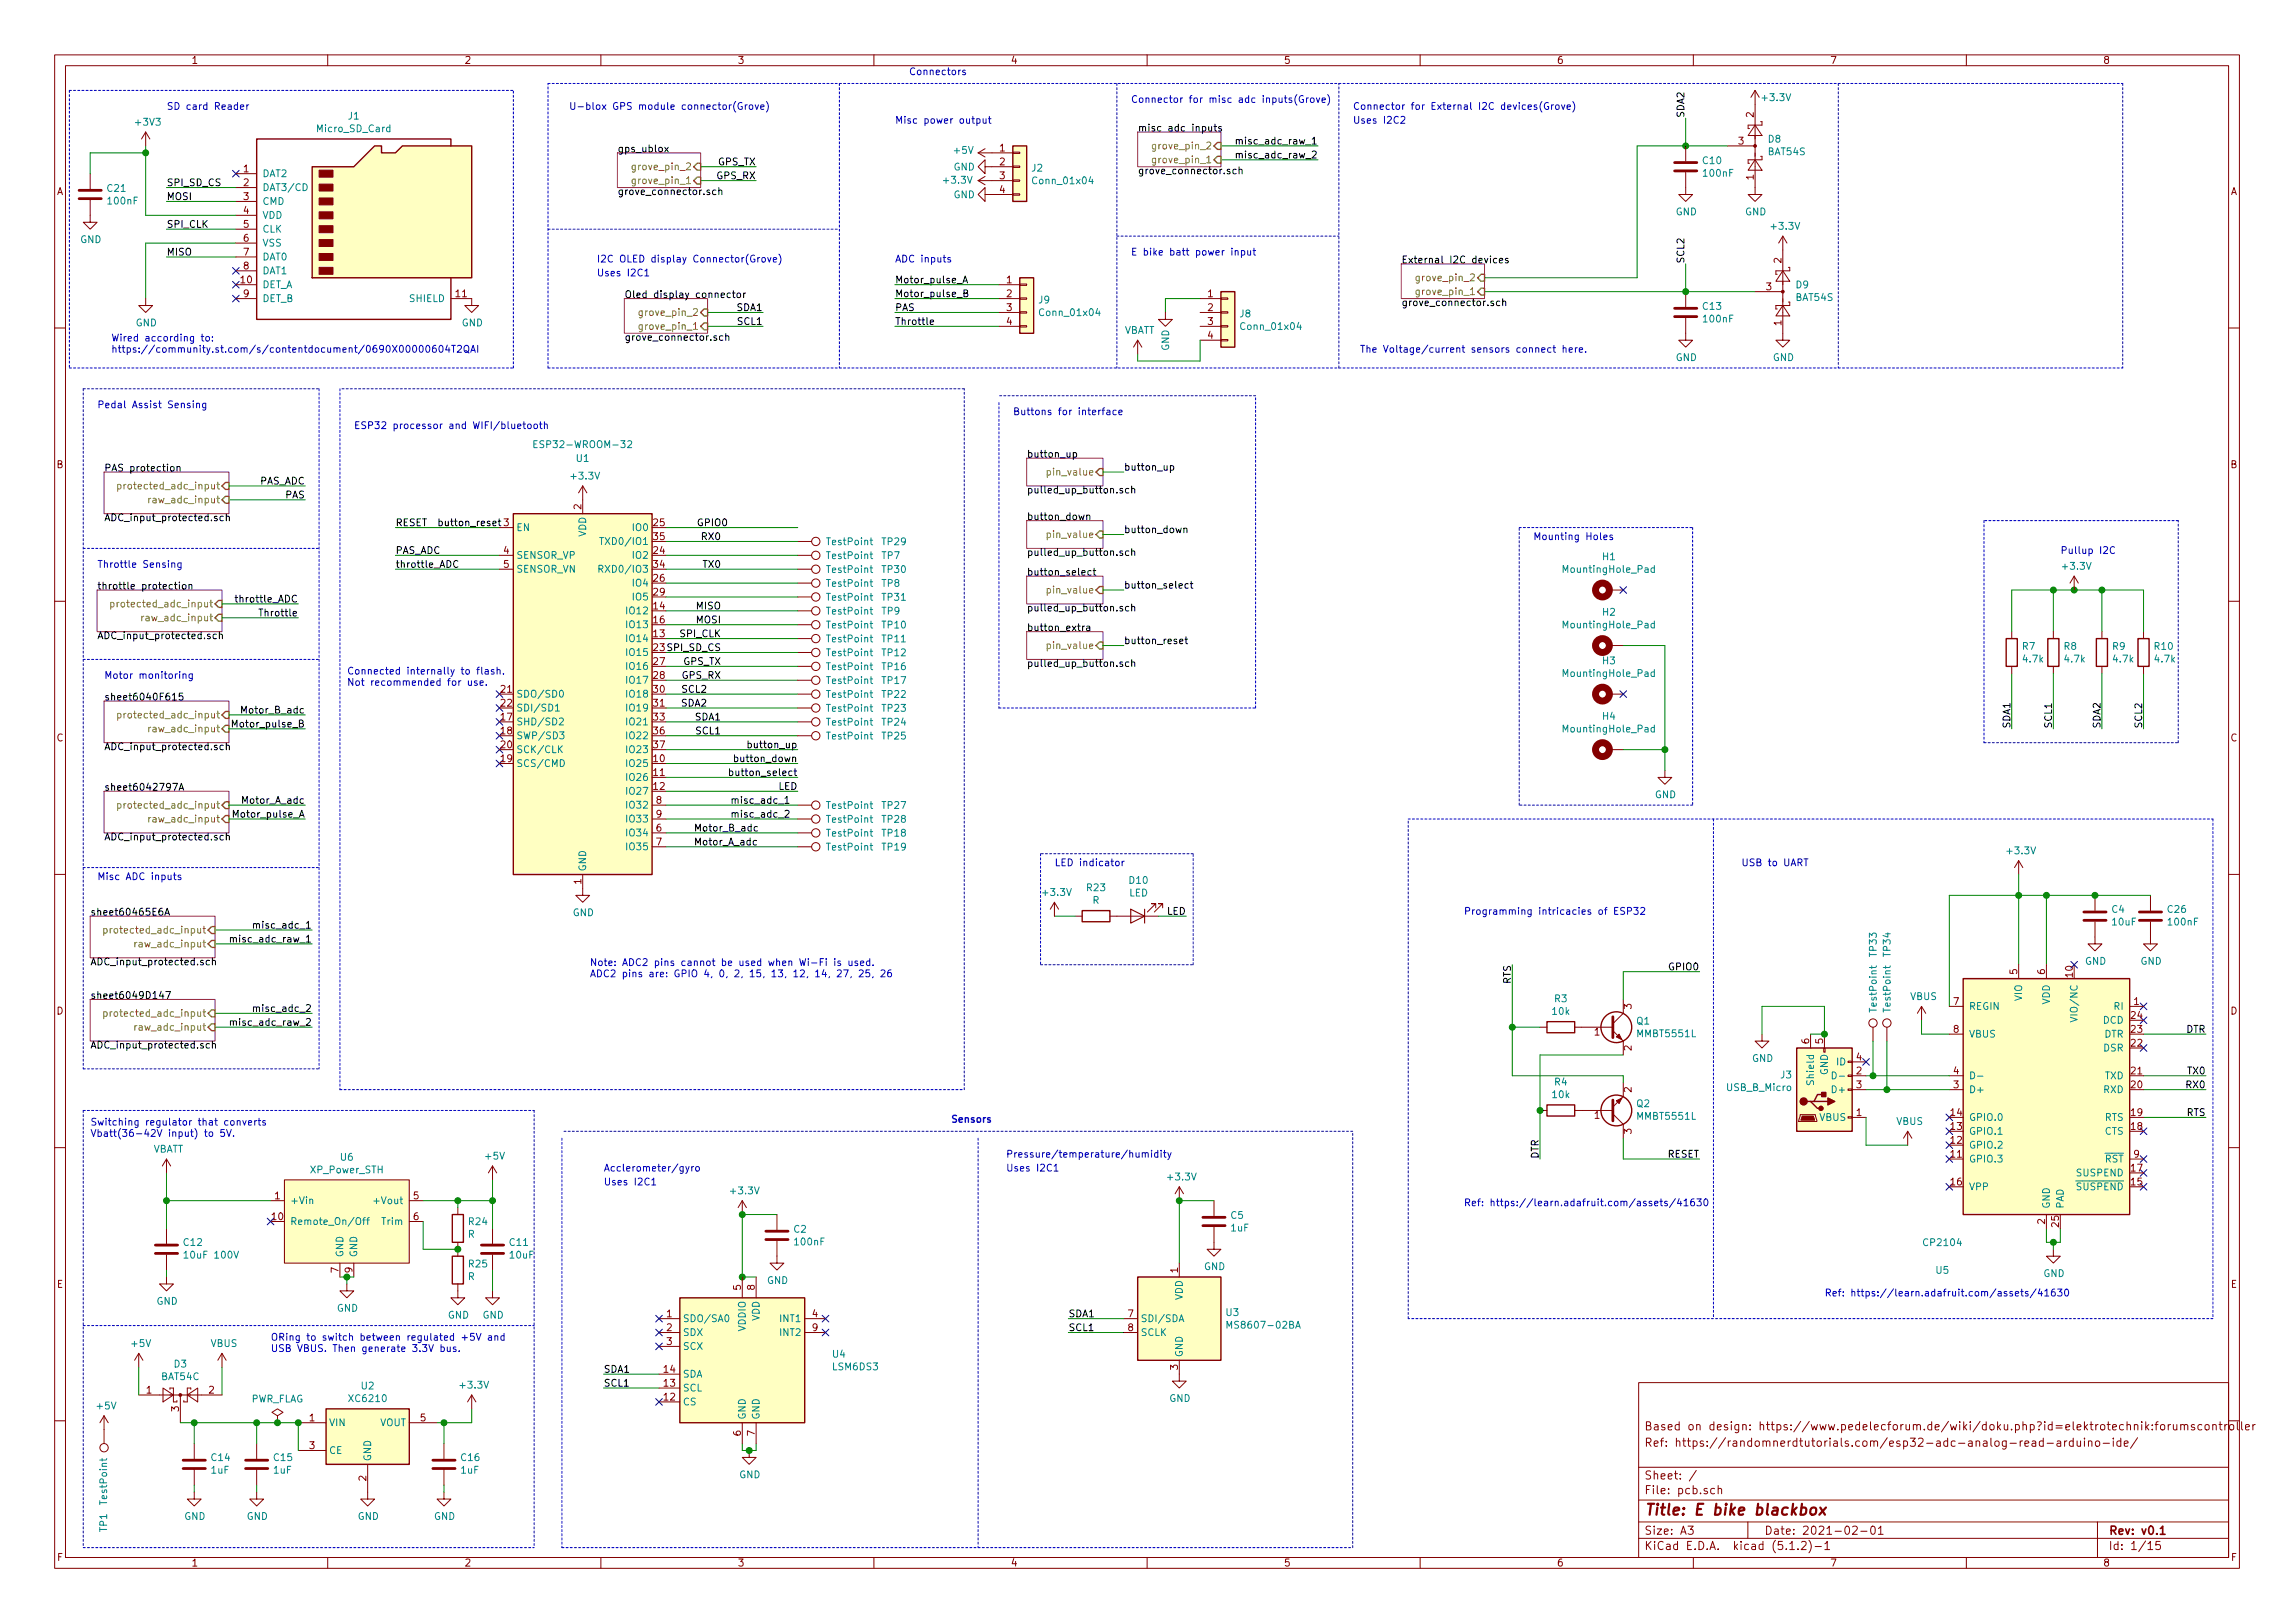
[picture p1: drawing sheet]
<svg xmlns="http://www.w3.org/2000/svg" width="420mm" height="297mm" viewBox="0 0 420 297" stroke-linecap="round" stroke-linejoin="round" font-family="sans-serif">
<defs><g id="words">
<text font-size="2.8" fill="#840000" x="301" y="277.3">Title: E bike blackbox</text>
<g font-size="2.1" fill="#840000">
<text x="301" y="261.8">Based on design: https://www.pedelecforum.de/wiki/doku.php?id=elektrotechnik:forumscontroller</text>
<text x="301" y="264.8">Ref: https://randomnerdtutorials.com/esp32-adc-analog-read-arduino-ide/</text>
<text x="301" y="273.5">File: pcb.sch</text>
<text x="301" y="270.8">Sheet: /</text>
<text x="301" y="280.9">Size: A3</text>
<text x="323" y="280.9">Date: 2021-02-01</text>
<text x="386" y="280.9">Rev: v0.1</text>
<text x="301" y="283.7">KiCad E.D.A. kicad (5.1.2)-1</text>
<text x="386" y="283.7">Id: 1/15</text>
</g>
<g font-size="1.8" fill="#840000">
<text x="35" y="11.7">1</text>
<text x="85" y="11.7">2</text>
<text x="135" y="11.7">3</text>
<text x="185" y="11.7">4</text>
<text x="235" y="11.7">5</text>
<text x="285" y="11.7">6</text>
<text x="335" y="11.7">7</text>
<text x="385" y="11.7">8</text>
<text x="321.1" y="21.5" transform="rotate(-90 321.1 21.5)">2</text>
<text x="183" y="27.7">1</text>
<text x="318.3" y="26.5">3</text>
<text x="10.4" y="35.7">A</text>
<text x="44.6" y="31.5">1</text>
<text x="44.6" y="34.1">2</text>
<text x="183" y="30.3">2</text>
<text x="183" y="32.8">3</text>
<text x="183" y="35.3">4</text>
<text x="321.1" y="32.9" transform="rotate(-90 321.1 32.9)">1</text>
<text x="408.4" y="35.7">A</text>
<text x="44.6" y="36.6">3</text>
<text x="44.6" y="39.2">4</text>
<text x="44.6" y="41.7">5</text>
<text x="44.6" y="44.2">6</text>
<text x="44.6" y="46.8">7</text>
<text x="44.1" y="51.9">10</text>
<text x="44.6" y="49.3">8</text>
<text x="184.3" y="51.9">1</text>
<text x="323.4" y="53.1">3</text>
<text x="326.1" y="48.1" transform="rotate(-90 326.1 48.1)">2</text>
<text x="44.6" y="54.4">9</text>
<text x="83.5" y="54.4">11</text>
<text x="184.3" y="54.4">2</text>
<text x="184.3" y="56.9">3</text>
<text x="184.3" y="59.5">4</text>
<text x="221.1" y="54.4">1</text>
<text x="221.1" y="56.9">2</text>
<text x="221.1" y="59.5">3</text>
<text x="326.1" y="59.6" transform="rotate(-90 326.1 59.6)">1</text>
<text x="221.1" y="62">4</text>
<text x="10.4" y="85.7">B</text>
<text x="408.4" y="85.7">B</text>
<text x="106.4" y="93.2" transform="rotate(-90 106.4 93.2)">2</text>
<text x="92.2" y="96.3">3</text>
<text x="92.2" y="101.4">4</text>
<text x="119.7" y="101.4">24</text>
<text x="119.7" y="96.3">25</text>
<text x="119.7" y="98.8">35</text>
<text x="92.2" y="103.9">5</text>
<text x="119.7" y="106.5">26</text>
<text x="119.7" y="103.9">34</text>
<text x="119.7" y="111.5">14</text>
<text x="119.7" y="109">29</text>
<text x="119.7" y="116.6">13</text>
<text x="119.7" y="114.1">16</text>
<text x="119.7" y="121.7">27</text>
<text x="119.7" y="124.2">28</text>
<text x="91.7" y="131.9">17</text>
<text x="91.7" y="126.8">21</text>
<text x="91.7" y="129.3">22</text>
<text x="119.7" y="126.8">30</text>
<text x="119.7" y="129.3">31</text>
<text x="119.7" y="131.9">33</text>
<text x="10.4" y="135.7">C</text>
<text x="91.7" y="134.4">18</text>
<text x="91.7" y="136.9">20</text>
<text x="119.7" y="134.4">36</text>
<text x="119.7" y="136.9">37</text>
<text x="408.4" y="135.7">C</text>
<text x="91.7" y="139.5">19</text>
<text x="119.7" y="139.5">10</text>
<text x="119.7" y="142">11</text>
<text x="119.7" y="144.6">12</text>
<text x="120.2" y="147.1">8</text>
<text x="120.2" y="149.6">9</text>
<text x="120.2" y="152.2">6</text>
<text x="120.2" y="154.7">7</text>
<text x="106.4" y="161.8" transform="rotate(-90 106.4 161.8)">1</text>
<text x="369.3" y="178.3" transform="rotate(-90 369.3 178.3)">5</text>
<text x="374.4" y="178.3" transform="rotate(-90 374.4 178.3)">6</text>
<text x="379.5" y="178.8" transform="rotate(-90 379.5 178.8)">10</text>
<text x="10.4" y="185.7">D</text>
<text x="298.7" y="184.7" transform="rotate(-90 298.7 184.7)">3</text>
<text x="357.7" y="183.9">7</text>
<text x="390.7" y="183.9">1</text>
<text x="408.4" y="185.7">D</text>
<text x="291.9" y="189.5">1</text>
<text x="331.2" y="191" transform="rotate(-90 331.2 191)">6</text>
<text x="333.8" y="191" transform="rotate(-90 333.8 191)">5</text>
<text x="357.7" y="189">8</text>
<text x="390.2" y="191.6">22</text>
<text x="390.2" y="189">23</text>
<text x="390.2" y="186.5">24</text>
<text x="298.7" y="192.3" transform="rotate(-90 298.7 192.3)">2</text>
<text x="339.9" y="196.6">2</text>
<text x="339.9" y="194.1">4</text>
<text x="357.7" y="196.6">4</text>
<text x="390.2" y="196.6">21</text>
<text x="298.7" y="199.9" transform="rotate(-90 298.7 199.9)">2</text>
<text x="339.9" y="199.2">3</text>
<text x="357.7" y="199.2">3</text>
<text x="390.2" y="199.2">20</text>
<text x="291.9" y="204.8">1</text>
<text x="298.7" y="207.5" transform="rotate(-90 298.7 207.5)">3</text>
<text x="339.9" y="204.3">1</text>
<text x="357.2" y="209.3">12</text>
<text x="357.2" y="206.8">13</text>
<text x="357.2" y="204.3">14</text>
<text x="390.2" y="206.8">18</text>
<text x="390.2" y="204.3">19</text>
<text x="357.2" y="211.9">11</text>
<text x="390.2" y="214.4">17</text>
<text x="390.7" y="211.9">9</text>
<text x="50.3" y="219.5">1</text>
<text x="75.7" y="219.5">5</text>
<text x="357.2" y="217">16</text>
<text x="390.2" y="217">15</text>
<text x="49.8" y="223.3">10</text>
<text x="75.7" y="223.3">6</text>
<text x="374.4" y="224" transform="rotate(-90 374.4 224)">2</text>
<text x="376.9" y="224.5" transform="rotate(-90 376.9 224.5)">25</text>
<text x="62" y="232.9" transform="rotate(-90 62 232.9)">7</text>
<text x="64.5" y="232.9" transform="rotate(-90 64.5 232.9)">9</text>
<text x="215.6" y="232.9" transform="rotate(-90 215.6 232.9)">1</text>
<text x="10.4" y="235.7">E</text>
<text x="135.6" y="236.1" transform="rotate(-90 135.6 236.1)">5</text>
<text x="138.2" y="236.1" transform="rotate(-90 138.2 236.1)">8</text>
<text x="408.4" y="235.7">E</text>
<text x="122.1" y="241.1">1</text>
<text x="122.1" y="243.6">2</text>
<text x="148.7" y="241.1">4</text>
<text x="148.7" y="243.6">9</text>
<text x="206.5" y="241.1">7</text>
<text x="206.5" y="243.6">8</text>
<text x="121.6" y="251.2">14</text>
<text x="122.1" y="246.2">3</text>
<text x="215.6" y="250.7" transform="rotate(-90 215.6 250.7)">3</text>
<text x="26.8" y="255.1">1</text>
<text x="38.3" y="255.1">2</text>
<text x="121.6" y="256.3">12</text>
<text x="121.6" y="253.8">13</text>
<text x="32.8" y="258.3" transform="rotate(-90 32.8 258.3)">3</text>
<text x="56.7" y="260.1">1</text>
<text x="77" y="260.1">5</text>
<text x="135.6" y="262.8" transform="rotate(-90 135.6 262.8)">6</text>
<text x="138.2" y="262.8" transform="rotate(-90 138.2 262.8)">7</text>
<text x="56.7" y="265.2">3</text>
<text x="67.1" y="271" transform="rotate(-90 67.1 271)">2</text>
<text x="10.5" y="285.7">F</text>
<text x="35" y="286.7">1</text>
<text x="85" y="286.7">2</text>
<text x="135" y="286.7">3</text>
<text x="185" y="286.7">4</text>
<text x="235" y="286.7">5</text>
<text x="285" y="286.7">6</text>
<text x="335" y="286.7">7</text>
<text x="385" y="286.7">8</text>
<text x="408.5" y="285.7">F</text>
</g>
<g font-size="1.8" fill="#0000c2">
<text x="166.4" y="13.8">Connectors</text>
<text x="30.5" y="20.1">SD card Reader</text>
<text x="104.1" y="20.1">U-blox GPS module connector(Grove)</text>
<text x="163.8" y="22.6">Misc power output</text>
<text x="207" y="18.8">Connector for misc adc inputs(Grove)</text>
<text x="247.6" y="20.1">Connector for External I2C devices(Grove)</text>
<text x="247.6" y="22.6">Uses I2C2</text>
<text x="207" y="46.8">E bike batt power input</text>
<text x="109.2" y="48">I2C OLED display Connector(Grove)</text>
<text x="109.2" y="50.6">Uses I2C1</text>
<text x="163.8" y="48">ADC inputs</text>
<text x="20.3" y="62.5">Wired according to:</text>
<text x="20.3" y="64.6">https://community.st.com/s/contentdocument/0690X00000604T2QAI</text>
<text x="248.9" y="64.6">The Voltage/current sensors connect here.</text>
<text x="17.8" y="74.7">Pedal Assist Sensing</text>
<text x="185.4" y="76">Buttons for interface</text>
<text x="64.8" y="78.5">ESP32 processor and WIFI/bluetooth</text>
<text x="280.7" y="98.8">Mounting Holes</text>
<text x="377.2" y="101.4">Pullup I2C</text>
<text x="17.8" y="103.9">Throttle Sensing</text>
<text x="19" y="124.2">Motor monitoring</text>
<text x="63.5" y="123.5">Connected internally to flash.</text>
<text x="63.5" y="125.5">Not recommended for use.</text>
<text x="17.8" y="161.1">Misc ADC inputs</text>
<text x="193" y="158.5">LED indicator</text>
<text x="318.8" y="158.5">USB to UART</text>
<text x="268" y="167.4">Programming intricacies of ESP32</text>
<text x="107.9" y="176.8">Note: ADC2 pins cannot be used when Wi-Fi is used.</text>
<text x="107.9" y="178.9">ADC2 pins are: GPIO 4, 0, 2, 15, 13, 12, 14, 27, 25, 26</text>
<text x="16.5" y="206">Switching regulator that converts</text>
<text x="16.5" y="208.1">Vbatt(36-42V input) to 5V.</text>
<text x="174" y="205.5">Sensors</text>
<text x="110.5" y="214.4">Acclerometer/gyro</text>
<text x="184.1" y="211.9">Pressure/temperature/humidity</text>
<text x="184.1" y="214.4">Uses I2C1</text>
<text x="110.5" y="217">Uses I2C1</text>
<text x="268" y="220.8">Ref: https://learn.adafruit.com/assets/41630</text>
<text x="334" y="237.3">Ref: https://learn.adafruit.com/assets/41630</text>
<text x="49.5" y="245.4">ORing to switch between regulated +5V and</text>
<text x="49.5" y="247.4">USB VBUS. Then generate 3.3V bus.</text>
</g>
<g font-size="1.8" fill="#008484">
<text x="25" y="23">+3V3</text>
<text x="63.8" y="21.9">J1</text>
<text x="322.8" y="18.5">+3.3V</text>
<text x="58.2" y="24.2">Micro_SD_Card</text>
<text x="174.8" y="28.2">+5V</text>
<text x="323.7" y="28.4">BAT54S</text>
<text x="323.7" y="26.1">D8</text>
<text x="19.7" y="35.1">C21</text>
<text x="48" y="32.4">DAT2</text>
<text x="48" y="35">DAT3/CD</text>
<text x="172.9" y="33.6">+3.3V</text>
<text x="174.6" y="31.2">GND</text>
<text x="188.9" y="31.4">J2</text>
<text x="189.4" y="33.7">Conn_01x04</text>
<text x="311.8" y="30">C10</text>
<text x="312" y="32.3">100nF</text>
<text x="19.9" y="37.4">100nF</text>
<text x="48" y="37.5">CMD</text>
<text x="48" y="40">VDD</text>
<text x="174.6" y="36.3">GND</text>
<text x="306.8" y="39.4">GND</text>
<text x="319.5" y="39.4">GND</text>
<text x="14.7" y="44.5">GND</text>
<text x="48" y="42.6">CLK</text>
<text x="48" y="45.1">VSS</text>
<text x="48" y="47.7">DAT0</text>
<text x="324.4" y="42">+3.3V</text>
<text x="48" y="52.7">DET_A</text>
<text x="48" y="50.2">DAT1</text>
<text x="328.8" y="52.8">D9</text>
<text x="24.8" y="59.7">GND</text>
<text x="48" y="55.3">DET_B</text>
<text x="75.1" y="55.3">SHIELD</text>
<text x="84.5" y="59.7">GND</text>
<text x="190.2" y="55.5">J9</text>
<text x="190.6" y="57.8">Conn_01x04</text>
<text x="227" y="58.1">J8</text>
<text x="311.8" y="56.7">C13</text>
<text x="312" y="59">100nF</text>
<text x="328.8" y="55.1">BAT54S</text>
<text x="205.7" y="61.1">VBATT</text>
<text x="214" y="64.2" transform="rotate(-90 214 64.2)">GND</text>
<text x="227.5" y="60.4">Conn_01x04</text>
<text x="306.8" y="66.1">GND</text>
<text x="324.6" y="66.1">GND</text>
<text x="98.8" y="82">ESP32-WROOM-32</text>
<text x="104.7" y="87.8">+3.3V</text>
<text x="105.6" y="84.5">U1</text>
<text x="94.5" y="97.2">EN</text>
<text x="107.3" y="98.3" transform="rotate(-90 107.3 98.3)">VDD</text>
<text x="111" y="99.7">TXD0/IO1</text>
<text x="116" y="97.2">IO0</text>
<text x="151.5" y="99.8">TestPoint</text>
<text x="161.6" y="99.8">TP29</text>
<text x="94.5" y="102.3">SENSOR_VP</text>
<text x="94.5" y="104.8">SENSOR_VN</text>
<text x="110.8" y="104.8">RXD0/IO3</text>
<text x="116" y="102.3">IO2</text>
<text x="116" y="107.4">IO4</text>
<text x="151.5" y="102.3">TestPoint</text>
<text x="151.5" y="107.4">TestPoint</text>
<text x="151.5" y="104.9">TestPoint</text>
<text x="161.5" y="102.3">TP7</text>
<text x="161.5" y="107.4">TP8</text>
<text x="161.6" y="104.9">TP30</text>
<text x="286.5" y="104.8">MountingHole_Pad</text>
<text x="293.4" y="102.5">H1</text>
<text x="377.8" y="104.3">+3.3V</text>
<text x="115" y="112.4">IO12</text>
<text x="116" y="109.9">IO5</text>
<text x="151.5" y="112.5">TestPoint</text>
<text x="151.5" y="109.9">TestPoint</text>
<text x="161.5" y="112.5">TP9</text>
<text x="161.6" y="109.9">TP31</text>
<text x="293.4" y="112.7">H2</text>
<text x="115" y="117.5">IO14</text>
<text x="115" y="115">IO13</text>
<text x="151.5" y="115">TestPoint</text>
<text x="151.5" y="117.6">TestPoint</text>
<text x="161.6" y="115">TP10</text>
<text x="161.6" y="117.6">TP11</text>
<text x="286.5" y="115">MountingHole_Pad</text>
<text x="370.3" y="118.9">R7</text>
<text x="377.9" y="118.9">R8</text>
<text x="386.8" y="118.9">R9</text>
<text x="394.5" y="118.9">R10</text>
<text x="115" y="120.1">IO15</text>
<text x="115" y="122.6">IO16</text>
<text x="115" y="125.1">IO17</text>
<text x="151.5" y="120.1">TestPoint</text>
<text x="151.5" y="125.2">TestPoint</text>
<text x="151.5" y="122.6">TestPoint</text>
<text x="161.6" y="120.1">TP12</text>
<text x="161.6" y="125.2">TP17</text>
<text x="161.6" y="122.6">TP16</text>
<text x="286.5" y="123.9">MountingHole_Pad</text>
<text x="293.4" y="121.6">H3</text>
<text x="370.5" y="121.2">4.7k</text>
<text x="378.1" y="121.2">4.7k</text>
<text x="387" y="121.2">4.7k</text>
<text x="394.6" y="121.2">4.7k</text>
<text x="94.5" y="127.7">SDO/SD0</text>
<text x="94.5" y="130.2">SDI/SD1</text>
<text x="115" y="127.7">IO18</text>
<text x="115" y="130.2">IO19</text>
<text x="151.5" y="130.3">TestPoint</text>
<text x="151.5" y="127.7">TestPoint</text>
<text x="161.6" y="130.3">TP23</text>
<text x="161.6" y="127.7">TP22</text>
<text x="293.4" y="131.7">H4</text>
<text x="94.5" y="132.8">SHD/SD2</text>
<text x="94.5" y="135.3">SWP/SD3</text>
<text x="94.5" y="137.8">SCK/CLK</text>
<text x="115" y="132.8">IO21</text>
<text x="115" y="135.3">IO22</text>
<text x="115" y="137.8">IO23</text>
<text x="151.5" y="135.3">TestPoint</text>
<text x="151.5" y="132.8">TestPoint</text>
<text x="161.6" y="135.3">TP25</text>
<text x="161.6" y="132.8">TP24</text>
<text x="286.5" y="134">MountingHole_Pad</text>
<text x="94.5" y="140.4">SCS/CMD</text>
<text x="115" y="140.4">IO25</text>
<text x="115" y="142.9">IO26</text>
<text x="115" y="145.5">IO27</text>
<text x="115" y="148">IO32</text>
<text x="151.5" y="148">TestPoint</text>
<text x="161.6" y="148">TP27</text>
<text x="303" y="146.1">GND</text>
<text x="115" y="153.1">IO34</text>
<text x="115" y="155.6">IO35</text>
<text x="115" y="150.5">IO33</text>
<text x="151.5" y="153.1">TestPoint</text>
<text x="151.5" y="155.7">TestPoint</text>
<text x="151.5" y="150.6">TestPoint</text>
<text x="161.6" y="153.1">TP18</text>
<text x="161.6" y="155.7">TP19</text>
<text x="161.6" y="150.6">TP28</text>
<text x="107.3" y="159.5" transform="rotate(-90 107.3 159.5)">GND</text>
<text x="206.8" y="161.8">D10</text>
<text x="367.6" y="156.3">+3.3V</text>
<text x="104.9" y="167.7">GND</text>
<text x="191.1" y="164">+3.3V</text>
<text x="199" y="163.1">R23</text>
<text x="200" y="165.4">R</text>
<text x="206.7" y="164.1">LED</text>
<text x="386.7" y="167.1">C4</text>
<text x="396.9" y="167.1">C26</text>
<text x="386.8" y="169.4">10uF</text>
<text x="397.1" y="169.4">100nF</text>
<text x="343.6" y="175" transform="rotate(-90 343.6 175)">TP33</text>
<text x="346.1" y="175" transform="rotate(-90 346.1 175)">TP34</text>
<text x="381.7" y="176.6">GND</text>
<text x="391.9" y="176.6">GND</text>
<text x="284.3" y="185.7">10k</text>
<text x="284.6" y="183.4">R3</text>
<text x="343.6" y="185" transform="rotate(-90 343.6 185)">TestPoint</text>
<text x="346.1" y="185" transform="rotate(-90 346.1 185)">TestPoint</text>
<text x="349.7" y="183">VBUS</text>
<text x="360.4" y="184.8">REGIN</text>
<text x="370.2" y="183.2" transform="rotate(-90 370.2 183.2)">VIO</text>
<text x="375.3" y="183.9" transform="rotate(-90 375.3 183.9)">VDD</text>
<text x="387.1" y="184.8">RI</text>
<text x="299.7" y="187.5">Q1</text>
<text x="299.9" y="189.8">MMBT5551L</text>
<text x="360.4" y="189.9">VBUS</text>
<text x="380.4" y="186.2" transform="rotate(-90 380.4 186.2)">VIO/NC</text>
<text x="385" y="187.4">DCD</text>
<text x="385.2" y="189.9">DTR</text>
<text x="320.8" y="194.3">GND</text>
<text x="326" y="197.4">J3</text>
<text x="334.6" y="196.8" transform="rotate(-90 334.6 196.8)">GND</text>
<text x="336.3" y="195">ID</text>
<text x="385.1" y="192.4">DSR</text>
<text x="385.3" y="197.5">TXD</text>
<text x="284.3" y="201">10k</text>
<text x="284.6" y="198.7">R4</text>
<text x="299.7" y="202.6">Q2</text>
<text x="316.2" y="199.7">USB_B_Micro</text>
<text x="332.1" y="198.1" transform="rotate(-90 332.1 198.1)">Shield</text>
<text x="335.8" y="200.1">D+</text>
<text x="360.4" y="200.1">D+</text>
<text x="385.1" y="200.1">RXD</text>
<text x="299.9" y="204.9">MMBT5551L</text>
<text x="333.2" y="205.1">VBUS</text>
<text x="347.2" y="205.9">VBUS</text>
<text x="360.4" y="207.7">GPIO.1</text>
<text x="360.4" y="205.1">GPIO.0</text>
<text x="385.3" y="207.7">CTS</text>
<text x="385.3" y="205.1">RTS</text>
<text x="27.9" y="211">VBATT</text>
<text x="56.9" y="214.7">XP_Power_STH</text>
<text x="62.4" y="212.4">U6</text>
<text x="89" y="212.2">+5V</text>
<text x="360.4" y="212.8">GPIO.3</text>
<text x="360.4" y="210.2">GPIO.2</text>
<text x="380.3" y="215.3">SUSPEND</text>
<text x="385.3" y="212.8">RST</text>
<text x="53.1" y="220.4">+Vin</text>
<text x="69" y="220.4">+Vout</text>
<text x="133.9" y="218.6">+3.3V</text>
<text x="213.9" y="216">+3.3V</text>
<text x="360.4" y="217.8">VPP</text>
<text x="375.3" y="221.3" transform="rotate(-90 375.3 221.3)">GND</text>
<text x="377.8" y="221.3" transform="rotate(-90 377.8 221.3)">PAD</text>
<text x="380.3" y="217.8">SUSPEND</text>
<text x="53.1" y="224.2">Remote_On/Off</text>
<text x="70.1" y="224.2">Trim</text>
<text x="85.7" y="226.5">R</text>
<text x="85.9" y="224.2">R24</text>
<text x="145.4" y="225.6">C2</text>
<text x="145.6" y="227.9">100nF</text>
<text x="225.4" y="223.1">C5</text>
<text x="225.4" y="225.4">1uF</text>
<text x="33.7" y="228">C12</text>
<text x="34.3" y="230.3">10uF 100V</text>
<text x="62.9" y="230.2" transform="rotate(-90 62.9 230.2)">GND</text>
<text x="65.4" y="230.2" transform="rotate(-90 65.4 230.2)">GND</text>
<text x="85.9" y="232">R25</text>
<text x="93.4" y="228">C11</text>
<text x="93.4" y="230.3">10uF</text>
<text x="220.4" y="232.4">GND</text>
<text x="352.4" y="228.1">CP2104</text>
<text x="354.5" y="233.1">U5</text>
<text x="374.1" y="233.7">GND</text>
<text x="28.7" y="238.8">GND</text>
<text x="85.7" y="234.3">R</text>
<text x="140.4" y="235">GND</text>
<text x="216.5" y="238" transform="rotate(-90 216.5 238)">VDD</text>
<text x="61.7" y="240.1">GND</text>
<text x="82" y="241.3">GND</text>
<text x="88.3" y="241.3">GND</text>
<text x="125" y="242">SDO/SA0</text>
<text x="125" y="244.5">SDX</text>
<text x="136.5" y="243.6" transform="rotate(-90 136.5 243.6)">VDDIO</text>
<text x="139.1" y="241.8" transform="rotate(-90 139.1 241.8)">VDD</text>
<text x="143" y="242">INT1</text>
<text x="143" y="244.5">INT2</text>
<text x="208.8" y="242">SDI/SDA</text>
<text x="208.8" y="244.5">SCLK</text>
<text x="224.5" y="240.9">U3</text>
<text x="225.4" y="243.2">MS8607-02BA</text>
<text x="24.2" y="246.5">+5V</text>
<text x="31.9" y="250.3">D3</text>
<text x="38.6" y="246.5">VBUS</text>
<text x="125" y="247.1">SCX</text>
<text x="152.5" y="248.5">U4</text>
<text x="152.6" y="250.8">LSM6DS3</text>
<text x="216.5" y="248.4" transform="rotate(-90 216.5 248.4)">GND</text>
<text x="17.8" y="257.9">+5V</text>
<text x="29.6" y="252.6">BAT54C</text>
<text x="45.8" y="256.7">PWR_FLAG</text>
<text x="64.1" y="256.6">XC6210</text>
<text x="66.2" y="254.3">U2</text>
<text x="84.4" y="254.1">+3.3V</text>
<text x="125" y="257.2">CS</text>
<text x="125" y="254.7">SCL</text>
<text x="125" y="252.1">SDA</text>
<text x="214.1" y="256.6">GND</text>
<text x="60.2" y="261">VIN</text>
<text x="69.5" y="261">VOUT</text>
<text x="136.5" y="259.9" transform="rotate(-90 136.5 259.9)">GND</text>
<text x="139.1" y="259.9" transform="rotate(-90 139.1 259.9)">GND</text>
<text x="38.7" y="269.7">1uF</text>
<text x="38.8" y="267.4">C14</text>
<text x="50.1" y="269.7">1uF</text>
<text x="50.2" y="267.4">C15</text>
<text x="60.2" y="266.1">CE</text>
<text x="67.9" y="267.5" transform="rotate(-90 67.9 267.5)">GND</text>
<text x="84.4" y="269.7">1uF</text>
<text x="84.5" y="267.4">C16</text>
<text x="19.6" y="275.2" transform="rotate(-90 19.6 275.2)">TestPoint</text>
<text x="135.3" y="270.5">GND</text>
<text x="19.6" y="280.3" transform="rotate(-90 19.6 280.3)">TP1</text>
<text x="33.7" y="278.2">GND</text>
<text x="45.2" y="278.2">GND</text>
<text x="65.5" y="278.2">GND</text>
<text x="79.5" y="278.2">GND</text>
</g>
<g font-size="1.8">
<text x="308.4" y="21.6" transform="rotate(-90 308.4 21.6)">SDA2</text>
<text x="113" y="27.9">gps_ublox</text>
<text x="208.3" y="24.1">misc adc inputs</text>
<text x="227.2" y="26.5">misc_adc_raw_1</text>
<text x="227.2" y="29">misc_adc_raw_2</text>
<text x="30.5" y="34.1">SPI_SD_CS</text>
<text x="113" y="35.7">grove_connector.sch</text>
<text x="131.2" y="32.8">GPS_RX</text>
<text x="131.4" y="30.3">GPS_TX</text>
<text x="208.3" y="31.9">grove_connector.sch</text>
<text x="30.5" y="41.7">SPI_CLK</text>
<text x="30.5" y="36.6">MOSI</text>
<text x="30.5" y="46.8">MISO</text>
<text x="163.8" y="51.9">Motor_pulse_A</text>
<text x="256.5" y="48.2">External I2C devices</text>
<text x="308.4" y="48.3" transform="rotate(-90 308.4 48.3)">SCL2</text>
<text x="114.3" y="54.5">Oled display connector</text>
<text x="135" y="56.9">SDA1</text>
<text x="135.2" y="59.5">SCL1</text>
<text x="163.8" y="59.5">Throttle</text>
<text x="163.8" y="56.9">PAS</text>
<text x="163.8" y="54.4">Motor_pulse_B</text>
<text x="256.5" y="56">grove_connector.sch</text>
<text x="114.3" y="62.4">grove_connector.sch</text>
<text x="188" y="83.8">button_up</text>
<text x="19" y="86.3">PAS protection</text>
<text x="47.4" y="88.7">PAS_ADC</text>
<text x="205.7" y="86.1">button_up</text>
<text x="19" y="95.4">ADC_input_protected.sch</text>
<text x="52.2" y="91.2">PAS</text>
<text x="188" y="90.3">pulled_up_button.sch</text>
<text x="188" y="95.2">button_down</text>
<text x="72.4" y="101.4">PAS_ADC</text>
<text x="72.4" y="96.3">RESET</text>
<text x="80" y="96.3">button_reset</text>
<text x="127.9" y="96.3">GPIO0</text>
<text x="128.7" y="98.8">RX0</text>
<text x="188" y="101.7">pulled_up_button.sch</text>
<text x="205.7" y="97.6">button_down</text>
<text x="17.8" y="107.9">throttle protection</text>
<text x="72.4" y="103.9">throttle_ADC</text>
<text x="128.8" y="103.9">TX0</text>
<text x="188" y="105.3">button_select</text>
<text x="205.7" y="107.7">button_select</text>
<text x="43.7" y="110.3">throttle_ADC</text>
<text x="48" y="112.8">Throttle</text>
<text x="127.6" y="111.5">MISO</text>
<text x="188" y="111.9">pulled_up_button.sch</text>
<text x="17.8" y="117">ADC_input_protected.sch</text>
<text x="119.7" y="119.2">23 SPI_SD_CS</text>
<text x="124.6" y="116.6">SPI_CLK</text>
<text x="127.6" y="114.1">MOSI</text>
<text x="188" y="115.5">button_extra</text>
<text x="205.7" y="117.9">button_reset</text>
<text x="124.9" y="124.2">GPS_RX</text>
<text x="125.1" y="121.7">GPS_TX</text>
<text x="188" y="122.1">pulled_up_button.sch</text>
<text x="19" y="128.2">sheet6040F615</text>
<text x="44.7" y="130.6">Motor_B_adc</text>
<text x="124.8" y="129.3">SDA2</text>
<text x="125" y="126.8">SCL2</text>
<text x="127.4" y="131.9">SDA1</text>
<text x="19" y="137.3">ADC_input_protected.sch</text>
<text x="43.1" y="133.1">Motor_pulse_B</text>
<text x="127.6" y="134.4">SCL1</text>
<text x="137.4" y="136.9">button_up</text>
<text x="368" y="133.4" transform="rotate(-90 368 133.4)">SDA1</text>
<text x="375.7" y="133.4" transform="rotate(-90 375.7 133.4)">SCL1</text>
<text x="384.6" y="133.4" transform="rotate(-90 384.6 133.4)">SDA2</text>
<text x="392.2" y="133.4" transform="rotate(-90 392.2 133.4)">SCL2</text>
<text x="134.5" y="142">button_select</text>
<text x="135" y="139.5">button_down</text>
<text x="19" y="144.7">sheet6042797A</text>
<text x="43.1" y="149.6">Motor_pulse_A</text>
<text x="44.7" y="147.1">Motor_A_adc</text>
<text x="134.7" y="147.1">misc_adc_1</text>
<text x="134.7" y="149.6">misc_adc_2</text>
<text x="142.5" y="144.6">LED</text>
<text x="19" y="153.8">ADC_input_protected.sch</text>
<text x="127" y="152.2">Motor_B_adc</text>
<text x="127" y="154.7">Motor_A_adc</text>
<text x="16.5" y="167.6">sheet60465E6A</text>
<text x="213.6" y="167.4">LED</text>
<text x="43.1" y="172.5">misc_adc_raw_1</text>
<text x="47.1" y="170">misc_adc_1</text>
<text x="16.5" y="176.7">ADC_input_protected.sch</text>
<text x="305.7" y="177.6">GPIO0</text>
<text x="16.5" y="182.8">sheet6049D147</text>
<text x="47.1" y="185.2">misc_adc_2</text>
<text x="276.6" y="180.1" transform="rotate(-90 276.6 180.1)">RTS</text>
<text x="16.5" y="191.9">ADC_input_protected.sch</text>
<text x="43.1" y="187.7">misc_adc_raw_2</text>
<text x="400.2" y="189">DTR</text>
<text x="400.6" y="196.6">TX0</text>
<text x="400.4" y="199.2">RX0</text>
<text x="400.3" y="204.3">RTS</text>
<text x="281.7" y="212.1" transform="rotate(-90 281.7 212.1)">DTR</text>
<text x="305.3" y="211.9">RESET</text>
<text x="195.6" y="243.6">SCL1</text>
<text x="195.6" y="241.1">SDA1</text>
<text x="110.5" y="251.2">SDA1</text>
<text x="110.5" y="253.8">SCL1</text>
</g>
<g font-size="1.8" fill="#848400">
<text x="211.6" y="29.9">grove_pin_1</text>
<text x="211.6" y="27.3">grove_pin_2</text>
<text x="116.3" y="33.7">grove_pin_1</text>
<text x="116.3" y="31.2">grove_pin_2</text>
<text x="259.8" y="51.5">grove_pin_2</text>
<text x="117.6" y="57.8">grove_pin_2</text>
<text x="259.8" y="54">grove_pin_1</text>
<text x="117.6" y="60.4">grove_pin_1</text>
<text x="23" y="89.6">protected_adc_input</text>
<text x="192.3" y="87">pin_value</text>
<text x="28" y="92.1">raw_adc_input</text>
<text x="192.3" y="98.5">pin_value</text>
<text x="21.7" y="111.2">protected_adc_input</text>
<text x="26.7" y="113.7">raw_adc_input</text>
<text x="192.3" y="108.6">pin_value</text>
<text x="192.3" y="118.8">pin_value</text>
<text x="23" y="131.5">protected_adc_input</text>
<text x="28" y="134">raw_adc_input</text>
<text x="23" y="148">protected_adc_input</text>
<text x="28" y="150.5">raw_adc_input</text>
<text x="20.4" y="170.9">protected_adc_input</text>
<text x="25.5" y="173.4">raw_adc_input</text>
<text x="20.4" y="186.1">protected_adc_input</text>
<text x="25.5" y="188.6">raw_adc_input</text>
</g>
</g></defs>
<g fill="none" stroke="#840000" stroke-width=".18">
<path d="M10 10h400v277h-400zM12 12h396v273.1h-396zM60 10v2M110 10v2M160 10v2M210 10v2M260 10v2M310 10v2M321.3 16.5v19.1h1.3l-1.3 1.3-1.3-1.3h1.3M321.3 16.5l-.8 1.3M321.3 16.5l.8 1.3M360 10v2"/>
<path d="M16.5 36.6v4.1h1.3l-1.3 1.2-1.3-1.2h1.3M16.5 31.8v2.8M26.7 24.2l-.8 1.2M26.7 24.2v2.5M26.7 24.2l.7 1.2M43.2 31.8h3.8M43.2 34.3h3.8M43.2 36.9h3.8M43.2 39.4h3.8M179.1 28l1.2 .7M179.1 28h6.3M179.1 33.1l1.2 .7"/>
<path d="M179.1 33.1h6.3M180.3 30.5v-1.3l-1.2 1.3 1.2 1.3v-1.3h5.1M180.3 35.6v-1.3l-1.2 1.3 1.2 1.3v-1.3h5.1M180.3 27.2l-1.2 .8M180.3 32.3l-1.2 .8M185.4 35.5h1.3v.2h-1.3zM185.4 32.9h1.3v.3h-1.3zM185.4 30.4h1.3v.2h-1.3zM185.4 27.8h1.3v.3h-1.3zM308.6 31.5v4.1h1.3l-1.3 1.3-1.3-1.3h1.3M308.6 26.7v2.8M316.2 26.7h5.1"/>
<path d="M321.3 29.2l1.3 2h-2.6zM321.3 22.9l1.3 1.9h-2.6zM322.3 28.6h.3v.6h-2.6v.7h.3M322.3 22.3h.3v.6h-2.6v.6h.3M26.7 54.6v1.3h1.2l-1.2 1.3-1.3-1.3h1.3M43.2 52.1h3.8M43.2 54.6h3.8M43.2 41.9h3.8M43.2 44.5h3.8M43.2 47h3.8M43.2 49.6h3.8M82.5 54.6h3.9v1.3h1.2l-1.2 1.3-1.3-1.3h1.3"/>
<path d="M182.9 52.1h3.8M182.9 54.6h3.8M182.9 57.2h3.8M182.9 59.7h3.8M186.7 59.6h1.3v.3h-1.3zM186.7 57.1h1.3v.2h-1.3zM186.7 54.5h1.3v.3h-1.3zM186.7 52h1.3v.2h-1.3zM213.4 57.2v1.3h1.2l-1.2 1.2-1.3-1.2h1.3M219.7 54.6h3.8M219.7 57.2h3.8M219.7 59.7h3.8"/>
<path d="M223.5 59.6h1.3v.3h-1.3zM223.5 57.1h1.3v.2h-1.3zM223.5 54.5h1.3v.3h-1.3zM308.6 58.2v4.1h1.3l-1.3 1.2-1.3-1.2h1.3M308.6 53.4v2.8M321.3 53.4h5.1M326.4 43.2v19.1h1.3l-1.3 1.2-1.3-1.2h1.3M326.4 55.9l1.3 1.9h-2.6zM326.4 49.6l1.3 1.9h-2.6zM326.4 43.2l-.8 1.3M326.4 43.2l.8 1.3M327.4 48.9h.3v.7h-2.6v.6h.3"/>
<path d="M327.4 55.3h.3v.6h-2.6v.7h.3M10 60h2M208.3 62.3l-.8 1.2M208.3 62.3v2.5M208.3 62.3l.7 1.2M219.7 62.3h3.8M223.5 62.1h1.3v.3h-1.3zM408 60h2M91.4 96.6h2.6M106.7 88.9v5.1M106.7 88.9l-.8 1.3M106.7 88.9l.7 1.3"/>
<path d="M146 99.1h2.6M10 110h2M91.4 101.6h2.6M91.4 104.2h2.6M146 111.8h2.6M146 114.3h2.6M146 116.9h2.6M146 119.4h2.6M146 101.6h2.6M146 106.7h2.6M146 109.3h2.6M146 104.2h2.6"/>
<path d="M294.6 108h2.6M294.6 118.1h2.6M368.3 115.6v1.3M375.9 115.6v1.3M379.7 105.4l-.7 1.3M379.7 105.4v2.6M379.7 105.4l.8 1.3M384.8 115.6v1.3M392.4 115.6v1.3M408 110h2M146 127h2.6M146 129.6h2.6"/>
<path d="M146 124.5h2.6M146 122h2.6M146 134.7h2.6M146 132.1h2.6M294.6 127h2.6M294.6 137.2h2.6M368.3 122v1.2M375.9 122v1.2M384.8 122v1.2M392.4 122v1.2M119.4 152.4h2.5M119.4 155h2.5"/>
<path d="M119.4 149.9h2.5M119.4 147.4h2.5M146 152.4h2.6M146 155h2.6M146 149.9h2.6M146 147.4h2.6M304.8 141v1.3h1.3l-1.3 1.2-1.3-1.2h1.3M369.6 157.5l-.8 1.3M369.6 157.5v2.6M369.6 157.5l.7 1.3M10 160h2M106.7 160.1v3.8h1.2l-1.2 1.2-1.3-1.2h1.3"/>
<path d="M193 165.1l-.7 1.3M193 165.1v2.6M193 165.1l.8 1.3M196.8 167.7h1.3M203.2 167.7h8.9M211.6 166.2v-.8h-.8h.8l-1.5 1.5M212.9 166.2v-.8h-.8h.8l-1.6 1.5M369.6 176.6v2.5M374.6 176.6v2.5M383.5 168.7v4.1h1.3l-1.3 1.2-1.2-1.2h1.2M383.5 163.9v2.8M393.7 168.7v4.1h1.3l-1.3 1.2-1.3-1.2h1.3"/>
<path d="M393.7 163.9v2.8M408 160h2M281.9 188h1.3M288.3 188h7M295.3 188.6l1.9 1.9v2.6M297.2 198.2v2.5l-1.9 1.9M297.2 182.9v2.6l-1.9 1.9M322.6 189.3v1.2h1.2l-1.2 1.3-1.3-1.3h1.3M331.5 189.3v2.5M333.9 191.8h.2v.8h-.2zM334 189.3v2.5M338.3 194.2h.8v.3h-.8z"/>
<path d="M338.3 196.8h.8v.2h-.8zM338.3 199.3h.8v.3h-.8zM339.1 199.4h2.5M339.1 196.9h2.5M339.1 194.3h2.5M342.9 188v2.5M345.4 188v2.5M351.8 184.2l-.8 1.3M351.8 184.2v2.5M351.8 184.2l.8 1.3M356.9 184.2h2.5M356.9 199.4h2.5"/>
<path d="M356.9 196.9h2.5M356.9 189.3h2.5M389.9 184.2h2.5M10 210h2M30.5 212.1v2.6M30.5 212.1l-.8 1.3M30.5 212.1l.7 1.3M49.5 219.7h2.6M52.1 215.9h22.8v15.3h-22.8zM74.9 219.7h2.6M90.2 213.4v2.5M90.2 213.4l-.8 1.3"/>
<path d="M90.2 213.4l.7 1.3M135.9 219.7l-.8 1.3M135.9 219.7v2.6M135.9 219.7l.8 1.3M215.9 217.2l-.8 1.3M215.9 217.2v2.5M215.9 217.2l.8 1.3M222.2 219.7v2.8M281.9 203.2h1.3M288.3 203.2h7M295.3 203.9l1.9 1.9v2.5M329.6 204h2.8l.2 1.3h-3.3z"/>
<path d="M338.3 204.4h.8v.2h-.8zM339.1 204.5h2.5M349.2 207l-.7 1.3M349.2 207v2.6M349.2 207l.8 1.3M389.9 212.1h2.5M408 210h2M30.5 233.7v1.3h1.2l-1.2 1.3-1.3-1.3h1.3M30.5 224.8v2.8M30.5 229.7v2.7M62.2 231.2v2.5M63.5 235v1.3h1.3l-1.3 1.2-1.3-1.2h1.3"/>
<path d="M64.8 231.2v2.5M74.9 223.6h2.6M83.8 235v2.5h1.3l-1.3 1.3-1.3-1.3h1.3M83.8 221v1.3M83.8 227.4v2.5M90.2 236.3v1.2h1.2l-1.2 1.3-1.3-1.3h1.3M90.2 224.8v2.8M90.2 229.7v2.7M135.9 233.7v3.8M138.4 233.7v3.8M142.2 227.1v4.1h1.3l-1.3 1.2-1.2-1.2h1.2M142.2 222.3v2.8"/>
<path d="M215.9 231.2v2.5M222.2 224.6v4h1.3l-1.3 1.3-1.2-1.3h1.2M374.6 222.3v2.5M375.9 228.6v1.3h1.3l-1.3 1.3-1.3-1.3h1.3M19 259.1v5.1M19 259.1l-.7 1.3M19 259.1l.8 1.3M25.4 247.7l-.8 1.3M25.4 247.7v2.5M25.4 247.7l.8 1.3M25.4 255.3h15.2M29.8 254l1.9 1.3-1.9 1.3z"/>
<path d="M31.1 254.3v-.3h.6v2.6h.7v-.3M33 255.3v5.1M34.3 255.3l1.9-1.3v2.6zM34.9 254.3v-.3h-.6v2.6h-.6v-.3M40.6 247.7l-.7 1.3M40.6 247.7v2.5M40.6 247.7l.8 1.3M50.8 259.1l1-.6-1-.7-1 .7 1 .6v1.3M86.4 255.3l-.8 1.3M86.4 255.3v2.5M86.4 255.3l.7 1.3M120.6 241.3h3.9"/>
<path d="M120.6 256.6h3.9M120.6 254h3.9M120.6 251.5h3.9M120.6 243.9h3.9M120.6 246.4h3.9M147.3 241.3h3.8M147.3 243.9h3.8M205.7 241.3h2.6M205.7 243.9h2.6M215.9 249v3.8h1.3l-1.3 1.2-1.3-1.2h1.3M300 253h108v32.1h-108zM10 260h2"/>
<path d="M35.6 273.1v1.3h1.2l-1.2 1.2-1.3-1.2h1.3M35.6 264.2v2.8M35.6 269v2.8M47 273.1v1.3h1.3l-1.3 1.2-1.3-1.2h1.3M47 264.2v2.8M47 269v2.8M50.8 260.4h.1M54.6 260.4h5.1M54.6 265.5h5.1M67.3 268v6.4h1.3l-1.3 1.2-1.3-1.2h1.3M74.9 260.4h5.1M81.3 273.1v1.3h1.2l-1.2 1.2-1.3-1.2h1.3"/>
<path d="M81.3 264.2v2.8M81.3 269v2.8M135.9 260.4v3.8M137.2 265.5v1.2h1.2l-1.2 1.3-1.3-1.3h1.3M138.4 260.4v3.8M300 278.5h108M300 274.5h108M300 268.5h108M309 279.3h1l-.5 .6 .4 .1v.7l-.2 .1-.7-.1M310.5 269.1l-1.2 2M313.9 272.5l-.4-.1-.3 .3 .1 .6 .2 .1 .4-.1M314.6 272.5a.37 .37 0 0 1 .6 .1v.8"/>
<path d="M314.6 271.9v1.5M320 278.5v3M339.2 279.5l.6-.2 .2 .4-.9 1.1h.9M342.6 279.5l.4-.2a.94 .94 0 0 1 0 1.5 .82 .82 0 0 1-.4-1.3zM343.9 279.7l.4-.4v1.5M369.8 263.7v1M370.3 263.7l-.5 .3M370.7 264.2l.7-.1-.1-.3-.4-.1-.2 .2 .1 .7h.5M372.1 263.8h.5l.1 .9M372.7 264.1h-.5l-.2 .2 .2 .4 .5-.1M374.1 263.8l-.5-.1-.2 .3v.6l.2 .1 .5-.1M374.1 263.2v1.5"/>
<path d="M374.8 264.1h1.1M376.6 263.8h.6l.1 .9M377.3 264.1h-.5a.29 .29 0 0 0-.3 .3 .29 .29 0 0 0 .3 .3l.5-.1M378 263.7v1M378.4 263.7l-.4 .3M379.6 263.8l-.5-.1-.3 .3 .1 .6 .2 .1 .5-.1M379.6 263.2v1.5M380.3 263.7v.8a.37 .37 0 0 0 .6 .1M380.9 263.7v1M381.6 263.2v.2M381.6 263.7v1M382.3 263.8h.1a.37 .37 0 0 1 .6 .1v.8"/>
<path d="M382.3 263.7v1M383.7 263.8l.2-.1 .4 .1v.8l-.2 .1-.4-.1zM384 278.5v6.6M385 264.1h1.2M386.9 263.2v.2M386.9 263.7v1M388.3 263.8l-.5-.1-.2 .3v.6l.2 .1 .5-.1M388.3 263.2v1.5M388.9 264.2l.7-.1-.1-.3-.4-.1-.2 .2 .1 .7h.5M390.8 260.8l.2-.1 .3 .1 .1 .9M391.3 263.1l-1.3 2M392.1 260.2v.2"/>
<path d="M392.1 260.7v1M392.8 260.2v1.5M393 261.1l.4 .6M393.4 260.7l-.6 .6M394 261.6v.1M394 260.8v.1M394.5 260.7h.6M395.1 260.2l-.4 .2v1.3M395.6 260.8l.2-.1 .4 .1 .1 .6-.1 .2-.4 .1-.2-.1zM397 260.7v1M397.4 260.7l-.4 .3M397.9 260.7l.1 .9 .3 .1 .2-.1"/>
<path d="M398.5 260.7v1M399.2 260.8h.1a.37 .37 0 0 1 .6 .1v.8M399.2 260.7v1M399.9 260.9l.2-.2 .4 .1v.9M401.8 260.8a.37 .37 0 0 0-.6 .1v.2l.6 .2v.1l-.2 .3-.4-.1M403.1 260.8l-.4-.1-.3 .3 .1 .6 .2 .1 .4-.1M403.7 260.8l.3-.1 .4 .1v.8l-.2 .1-.5-.1zM405.1 260.8l.2-.1 .4 .1v.9M405.1 260.7v1M406.2 260.7h.6M406.5 260.2v1.3l.3 .2M407.3 260.7v1"/>
<path d="M407.7 260.7l-.3 .1-.1 .2M408 260h2M408.2 260.8l.3-.1 .4 .1v.8l-.2 .1-.5-.1zM409.6 260.2v1.3l.2 .2M410.4 260.2v1.3l.2 .2M411.1 261.2l.7-.1-.1-.3-.4-.1-.2 .2 .1 .7h.5M412.4 260.7v1M412.9 260.7l-.5 .3M60 285.1v1.9M110 285.1v1.9M160 285.1v1.9M210 285.1v1.9"/>
<path d="M260 285.1v1.9M300 281.5h108M310 285.1v1.9M327.7 283.6h.8M329.2 283.5v.1M329.8 282.3l.2-.2h.4l.2 .2 .1 .2-.1 .2-.9 .9h1M331.2 281.9a1.71 1.71 0 0 1 0 2.3M332.3 283h1.2M334.1 282.5l.4-.4v1.5M334.1 283.6h.8M340.7 280.2h1.1M343.9 280.8h.9"/>
<path d="M360 285.1v1.9M393.2 282.5l.5-.4v1.5M393.2 283.6h.9M395.5 282.1h-.8v.7l.2-.1h.5l.1 .3v.5l-.3 .1-.5-.1"/>
<circle cx="149.4" cy="99.1" r=".76"/>
<circle cx="149.4" cy="114.3" r=".76"/>
<circle cx="149.4" cy="116.9" r=".76"/>
<circle cx="149.4" cy="119.4" r=".76"/>
<circle cx="149.4" cy="104.2" r=".76"/>
<circle cx="149.4" cy="109.3" r=".76"/>
<circle cx="149.4" cy="106.7" r=".76"/>
<circle cx="149.4" cy="101.6" r=".76"/>
<circle cx="149.4" cy="111.8" r=".76"/>
<circle cx="149.4" cy="129.6" r=".76"/>
<circle cx="149.4" cy="127" r=".76"/>
<circle cx="149.4" cy="132.1" r=".76"/>
<circle cx="149.4" cy="124.5" r=".76"/>
<circle cx="149.4" cy="122" r=".76"/>
<circle cx="149.4" cy="134.7" r=".76"/>
<circle cx="149.4" cy="152.4" r=".76"/>
<circle cx="149.4" cy="155" r=".76"/>
<circle cx="149.4" cy="147.4" r=".76"/>
<circle cx="149.4" cy="149.9" r=".76"/>
<circle cx="342.9" cy="187.2" r=".76"/>
<circle cx="345.4" cy="187.2" r=".76"/>
<circle cx="19" cy="265" r=".76"/>
</g>
<path d="M395.5 279.7l.4-.4v1.5M395.5 280.8h.9" fill="none" stroke="#840000" stroke-width=".3"/>
<path d="M331.6 276.1a.51 .51 0 0 1 .5-.2 .51 .51 0 0 1 .4 .4v.5a.56 .56 0 0 1-.6 .4 .56 .56 0 0 1-.5-.4zM333.2 275.9l.9 1.3M334.3 275.9l-1.2 1.3" fill="none" stroke="#840000" stroke-width=".41"/>
<g fill="none" stroke="#008400" stroke-width=".18">
<path d="M26.7 26.7v12.7h16.5M26.7 28h-10.2v3.8M30.5 36.9h12.7M30.5 34.3h12.7M128.3 30.5h10.1M128.3 33.1h10.1M223.5 26.7h17.8M223.5 29.2h17.8M308.6 21.6v5.1M316.2 26.7h-16.5v24.1h-27.9M30.5 47h12.7M30.5 41.9h12.7"/>
<path d="M43.2 44.5h-16.5v10.1M129.5 59.7h10.2M129.5 57.2h10.2M163.8 59.7h19.1M163.8 57.2h19.1M163.8 54.6h19.1M163.8 52.1h19.1M219.7 54.6h-6.3v2.6M271.8 53.4h49.5M308.6 48.3v5.1M219.7 62.3v3.8h-11.4v-1.3M41.9 91.5h14"/>
<path d="M41.9 88.9h14M72.4 96.6h19M121.9 96.6h24.1M121.9 99.1h24.1M201.9 86.4h3.8M201.9 97.8h3.8M40.6 110.5h14M40.6 113.1h14M72.4 104.2h19M72.4 101.6h19M121.9 104.2h24.1M121.9 101.6h24.1"/>
<path d="M121.9 106.7h24.1M121.9 119.4h24.1M121.9 116.9h24.1M121.9 114.3h24.1M121.9 111.8h24.1M121.9 109.3h24.1M201.9 118.1h3.8M201.9 108h3.8M297.2 118.1h7.6v22.9M368.3 115.6v-7.6h24.1v7.6M375.9 108v7.6M384.8 108v7.6"/>
<path d="M41.9 130.8h14M41.9 133.4h14M121.9 132.1h24.1M121.9 134.7h24.1M121.9 127h24.1M121.9 129.6h24.1M121.9 137.2h24.1M121.9 124.5h24.1M121.9 139.7h24.1M121.9 122h24.1M297.2 137.2h7.6M368.3 123.2v10.2"/>
<path d="M375.9 123.2v10.2M384.8 123.2v10.2M392.4 123.2v10.2M41.9 147.4h14M41.9 149.9h14M121.9 142.3h24.1M121.9 144.8h24.1M121.9 152.4h24.1M121.9 155h24.1M121.9 147.4h24.1M121.9 149.9h24.1M39.4 172.8h17.7"/>
<path d="M39.4 170.2h17.7M193 167.7h3.8M212.1 167.7h5.1M276.9 176.6v20.3h20.3v1.3M311.1 177.8h-13.9v5.1M369.6 160.1v16.5M374.6 163.9v12.7M393.7 163.9h-36.8v20.3M39.4 188h17.7M39.4 185.5h17.7M276.9 188h5M297.2 193.1h-15.3v19"/>
<path d="M322.6 189.3v-5.1h11.4v5.1h-2.5M341.6 196.9h15.3M341.6 199.4h15.3M342.9 190.5v6.4M345.4 190.5v8.9M351.8 186.7v2.6h5.1M392.4 196.9h11.5M392.4 199.4h11.5M392.4 189.3h11.5M30.5 219.7h19M30.5 214.7v10.1M77.5 219.7h12.7"/>
<path d="M83.8 219.7v1.3M90.2 215.9v8.9M222.2 219.7h-6.3v11.5M297.2 208.3v3.8h13.9M341.6 204.5v5.1h7.6M392.4 204.5h11.5M30.5 232.4v1.3M62.2 233.7h2.6M63.5 233.7v1.3M77.5 223.6v5h6.3M90.2 232.4v3.9M142.2 222.3h-6.3v11.4h2.5"/>
<path d="M374.6 224.8v2.6h2.6v-2.6M375.9 227.4v1.2M25.4 250.2v5.1M40.6 250.2v5.1M86.4 257.8v2.6h-6.4M110.5 254h10.1M110.5 251.5h10.1M195.6 243.9h10.1M195.6 241.3h10.1M33 260.4h21.6v5.1M35.6 260.4v3.8M35.6 271.8v1.3"/>
<path d="M47 260.4v3.8M47 271.8v1.3M81.3 260.4v3.8M81.3 271.8v1.3M135.9 264.2v1.3h2.5v-1.3"/>
</g>
<g fill="none" stroke="#0000c2" stroke-width=".18">
<path d="M44 19.6l.6-.1v-.3h-.4l-.2 .2 .1 .6h.5M45.2 19.2v.8M45.5 19.2h-.2l-.1 .2M134.7 18.6a1.4 1.4 0 0 0 0 1.9M135.8 18.8a.59 .59 0 0 0-.7 .6 .59 .59 0 0 0 .7 .6l.1-.5h-.2M136.4 19.2v.8M136.8 19.2h-.2l-.2 .2M137.3 19.2h.3l.2 .1-.1 .7h-.3l-.2-.2zM138.3 19.2l.3 .8 .3-.8M139.3 19.6l.6-.1-.1-.3h-.3l-.2 .2v.6h.5M140.3 18.6a1.47 1.47 0 0 1 0 1.9M176.7 12.9l-.3-.1-.2 .2 .1 .2 .4 .1v.3h-.5"/>
<path d="M237.4 17.3a1.4 1.4 0 0 0 0 1.9M238.6 17.6a.59 .59 0 0 0-.8 .5 .59 .59 0 0 0 .8 .6v-.5h-.2M239.2 17.9v.9M239.5 17.9l-.3 .2M240 18l.3-.1 .3 .2-.1 .6-.3 .1-.3-.3zM241 17.9l.3 .9 .3-.9M242 18.3l.6-.1v-.2l-.4-.1-.2 .2 .1 .6h.5M243.1 17.3a1.47 1.47 0 0 1 0 1.9M282.3 18.6a1.47 1.47 0 0 0 0 1.9M283.5 18.8a.59 .59 0 0 0-.8 .6 .59 .59 0 0 0 .8 .6v-.5h-.2M284 19.2v.8M284.4 19.2l-.4 .2"/>
<path d="M284.8 19.3l.2-.1 .4 .1v.5l-.1 .2h-.3l-.2-.1zM285.9 19.2l.3 .8 .3-.8M286.9 19.6l.6-.1v-.3h-.4l-.2 .2 .1 .6h.5M287.9 18.6a1.47 1.47 0 0 1 0 1.9M178.8 21.8l.4-.1 .2 .3-.1 .5h-.5M178.8 21.7v1.3M180 21.7v.8l.3 .1 .2-.2M180.5 21.7v.9M180.9 21.7h.5M181.1 21.3v1.1l.3 .2M256.5 21.4l.5-.1 .2 .4-.1 .2-.7 .7h.8M118.1 49.6l.3-.4v1.3"/>
<path d="M118.1 50.5h.7M138.7 47.1v.9M139.1 47.1l-.4 .3M139.6 47.2l.3-.1 .2 .3-.1 .5-.3 .1-.2-.2zM140.5 47.1l.3 .9 .3-.9M141.6 47.5l.6-.1-.1-.2-.3-.1-.2 .2v.6h.5M142.6 46.5a1.4 1.4 0 0 1 0 1.9M174 47.2l-.3-.1-.2 .2 .1 .2 .4 .1v.3h-.5M226.1 46l.2-.1h.3l.1 .8M226.1 45.9v.8M227.3 45.9h.3l.3 .2-.1 .5h-.5M227.3 45.9v1.2"/>
<path d="M228.4 45.9l.1 .7 .3 .1 .2-.1M229 45.9v.8M229.4 45.9h.5M229.6 45.4v1.1l.3 .2M35.4 73.4v.1M35.4 73.8v.8M36 73.9l.2-.1h.3v.8M36 73.8v.8M36.8 61.6h.5M37 61.1v1.1l.3 .2M37.7 73.8l-.1 1.1-.2 .2-.3-.1M37.7 73.8h-.4l-.2 .2 .1 .6h.5"/>
<path d="M37.8 61.6h.3l.3 .2-.2 .6h-.3l-.2-.2zM38.9 62.3v.1M38.9 61.6v.2M74.4 63.3l.2-.1a.67 .67 0 0 1 .5 .6 .67 .67 0 0 1-.5 .7l-.3-.5zM75.7 63.3l.1-.1a.67 .67 0 0 1 .5 .6 .67 .67 0 0 1-.5 .7l-.2-.3-.1-.2zM76.9 63.3l.1-.1a.67 .67 0 0 1 .5 .6 .67 .67 0 0 1-.5 .7l-.2-.5zM78.1 63.3l.2-.1a.67 .67 0 0 1 .4 .6 .67 .67 0 0 1-.4 .7l-.3-.5zM79.8 63.2l-.4 .1a.87 .87 0 0 0 0 1.2l.4-.2v-.5l-.4-.1-.2 .2M80.5 63.3l.2-.1a.67 .67 0 0 1 .4 .6 .67 .67 0 0 1-.4 .7l-.3-.5zM81.9 63.2l-.3 .8h.8M82.2 63.6v.9M82.7 63.2h.7"/>
<path d="M83 63.2v1.3M83.8 63.3l.5-.1 .2 .4-.1 .2-.7 .7h.8M85 63.4l.3-.2a.45 .45 0 0 1 .5 .4l-.2 .8h-.4a.92 .92 0 0 1-.2-1zM85.2 64.2l.7 .4M86.2 64.5l.4-1.3 .4 1.3M86.3 64.1h.6M87.5 63.2v1.3M94.8 78l.6-.1-.1-.2-.4-.1-.1 .2v.6h.5M95.7 77.6h.5M95.9 77.2v1.1l.3 .1M96.7 77.7l.3-.1 .3 .2-.2 .6h-.3l-.2-.1zM97.8 77.7l.3-.1 .2 .1 .1 .5-.1 .2h-.3l-.2-.1z"/>
<path d="M98.8 77.6h.4M98.9 77.2v1.1l.3 .1M99.7 77.7l.1-.1 .4 .1v.7M99.7 77.2v1.2M201.8 75.1h.4M202.2 74.6l-.3 .2v1.1M202.7 75.1h.4l.1 .8M203.2 75.4h-.4l-.2 .2 .2 .3h.4M204.3 75.1h-.3l-.2 .2 .1 .6h.4M204.8 75.5l.6-.1v-.3h-.4l-.2 .1 .1 .7h.5M282.2 64l.7-.1-.1-.2-.4-.1-.2 .2 .1 .6h.5M283.9 63.7l-.3-.1-.3 .3 .2 .5h.4"/>
<path d="M284.3 63.6h.5M284.5 63.2v1.1l.3 .2M286.2 63.8l.2-.2 .3 .1v.8M286.2 63.2v1.3M287.3 64l.6-.1-.1-.2-.3-.1-.2 .2v.6h.5M288.4 63.6v.9M288.8 63.6l-.4 .3M289.1 64l.6-.1v-.2l-.4-.1-.2 .2 .1 .6h.5M290.3 64.3v.2M293.6 98.3l.6-.1v-.2l-.4-.1-.2 .2 .1 .6h.5M295.2 98l-.3-.1-.2 .2 .1 .2 .4 .1v.3h-.5M31.4 103.1l.2-.1 .3 .1 .1 .7"/>
<path d="M31.4 103v.8M33.1 103v1.2l-.2 .1-.3-.1M33.1 103.1l-.3-.1-.3 .2 .2 .6h.4M387.1 100.2a.51 .51 0 0 0-.6 0 .51 .51 0 0 0-.2 .6l.3 .5 .5-.1M32.9 122.9v.1M32.9 123.3v.9M33.5 123.5l.2-.2 .3 .1 .1 .8M33.5 123.3v.9M35.2 123.3v1l-.2 .3-.4-.1M35.2 123.4l-.4-.1-.2 .3 .1 .5h.5M85.8 124.6v.8h.3l.2-.1M86.3 124.6v.8"/>
<path d="M87.3 122.5h.5M87.3 124.6h-.3l-.2 .2 .1 .2 .4 .1v.3h-.5M87.8 122.1l-.3 .2v1.1M87.9 125l.6-.1-.1-.3h-.3l-.2 .2v.6h.5M88.2 122.1v1.1l.2 .2M88.8 122.6h.5l.1 .8M89 125.3v.1M89.4 122.8l-.4 .1-.2 .2 .2 .3 .4-.1M90.4 122.6l-.3-.1-.2 .2 .1 .2 .4 .1v.3h-.5M91 122.7l.2-.2 .3 .1 .1 .8M91 122.1v1.3M92.2 123.3v.1"/>
<path d="M31.9 159.7v1.1l.3 .2M204.3 157.7l.3-.1 .3 .2-.1 .6-.3 .1-.2-.2zM205.4 157.6v.9M205.8 157.6l-.4 .2M330.3 157.2h.7M330.6 157.2v1.3M31.7 160.2h.5M33.1 160.2h-.3l-.2 .1 .1 .2 .4 .1v.3h-.5M150.2 176.1h.4M150.8 175.4h-.6v1.3M151.3 175.4v.2M151.3 175.9v.8"/>
<path d="M151.9 178.7l-.2 .3M152.8 175.4v.2M152.8 175.9v.8M153.3 177.6l.5-.1 .2 .4v.2l-.8 .7h.8M153.8 175.9h-.3l-.1 .2v.1l.4 .2v.3h-.4M154.5 177.5h.8l-.5 1.3M155.4 175.9l.1 .8h.3l.2-.1M155.9 178.7l-.2 .3M156 175.9v.8M157 175.9h-.3l-.2 .2 .1 .1 .4 .2v.3h-.5M157.3 177.6l.5-.1 .2 .4-.7 .9h.7M157.5 176.3l.6-.1v-.3h-.4l-.2 .2 .1 .6h.5"/>
<path d="M159.2 177.5h-.6l-.1 .6 .2-.1 .5 .1v.5l-.2 .2-.5-.2M159.2 175.9h-.3l-.3 .2 .1 .6h.5M159.2 175.4v1.3M159.8 176.6v.1M159.8 178.7l-.1 .3M161.3 177.6l.5-.1 .2 .4-.8 .9h.8M163.1 177.5l-.4 .1a.87 .87 0 0 0 0 1.2l.5-.2v-.5l-.5-.1-.2 .2M295.6 166.7h.4M296.2 166.1h-.6v1.2h.6M297.4 166.2l-.4-.1-.3 .1v.4l.6 .2 .1 .3-.2 .2h-.5M298 166.7h.6l.1-.2-.1-.3-.6-.1v1.2M299.1 166.1h.8l-.4 .5 .3 .1v.6h-.5l-.2-.1"/>
<path d="M300.4 166.2l.5-.1 .2 .3v.2l-.8 .7h.8M37.4 207.1h.5M37.6 206.7v1.1l.3 .2M38.4 207.2l.3-.1 .2 .2-.1 .6-.3 .1-.2-.2zM41.1 206.7h-.6l-.1 .6 .2-.1 .5 .1v.6l-.2 .1-.5-.1M41.5 206.7l.4 1.3 .4-1.3M42.3 205.2l.2-.1 .3 .1 .1 .5-.2 .2h-.2l-.2-.1zM42.7 207.9v.1M43.4 205.2l.2-.1h.3l.1 .8M43.4 205.1v.8M44.4 205.1l.4 .8 .3-.8M45.5 205.5l.6-.1-.1-.3h-.3l-.2 .2v.6h.5"/>
<path d="M46.6 205.1v.8M47 205.1l-.4 .2M47.2 205.1h.5M47.4 204.7v1.1l.3 .1M48.6 205.1h-.3l-.2 .2v.1l.5 .2v.3h-.5M119.3 216l.4-.4v1.3M119.3 216.9h.7M125.6 213.5l.3 .8M126.2 213.5l-.5 1.1-.1 .2M126.6 213.5v.8M127 213.5l-.4 .2M127.5 213.5h.3l.2 .2-.1 .6h-.3l-.2-.2z"/>
<path d="M193 213.4l.3-.3v1.2M193 214.3h.7M209.1 211.1l.2-.1h.3l.1 .8M209.1 211v.8M209.7 211.1l.2-.1h.3v.8M210.8 210.5v.2M210.8 211v.8M212 211h-.4l-.2 .2 .1 .5h.5M212 210.5v1.3M212.6 210.5v.2M212.6 211v.8M213 211h.5"/>
<path d="M213.2 210.5v1.1l.3 .2M213.8 211l.3 .8M214.4 211l-.4 1.1-.2 .1M303.9 219.8h.5M304.1 219.4v1.1l.3 .2M305.2 219.9l-.3-.1-.2 .2 .1 .2 .4 .1v.3h-.5M306.7 219.4l-1.1 1.6M307.4 219.4l-.3 .9h.8M307.7 219.8v.9M308.3 219.8l.4-.4v1.3M310.1 219.4l-.3 .1a.87 .87 0 0 0 0 1.2l.4-.1v-.6l-.4-.1-.3 .3M310.7 219.4h.8l-.5 .5 .4 .1v.6l-.2 .1-.5-.1"/>
<path d="M312.1 219.5l.1-.1a.67 .67 0 0 1 .5 .7 .67 .67 0 0 1-.5 .6l-.2-.2-.1-.3zM302.9 220.3l.6-.1v-.3l-.4-.1-.2 .2 .1 .6h.5M308.3 220.7h.7M369 236.8l.6-.1-.1-.3h-.4l-.1 .1v.6h.5M369.9 236.4h.5M370.1 235.9v1.1l.3 .2M371.3 236.4h-.3l-.2 .1v.2l.5 .1v.3h-.5M372.8 235.9l-1.1 1.6M373.5 235.9l-.3 .9h.7M373.7 236.4v.8M374.3 236.3l.4-.4v1.3M374.3 237.2h.8"/>
<path d="M376.2 235.9l-.4 .1a.87 .87 0 0 0 0 1.2l.4-.1v-.6l-.4-.1-.2 .3M376.7 235.9h.8l-.4 .5 .3 .1v.6l-.1 .1-.6-.1M378.1 236.1l.2-.2a.67 .67 0 0 1 .4 .7 .67 .67 0 0 1-.4 .6l-.3-.2v-.3zM80.7 246.6l.4-.1 .3 .2-.2 .6h-.5M80.7 246.1v1.3M81.9 246.5v.8l.3 .1 .2-.2M82.4 246.5v.9M83.5 246.6l-.3-.1-.2 .2v.2l.5 .1v.3h-.5M84.1 247.2v.2M84.6 244.8h1M85.1 244.3v1M86.8 244h-.6l-.1 .6 .2-.1 .5 .1v.6l-.2 .1-.5-.1"/>
<path d="M87.2 244l.4 1.3 .5-1.3M89.5 244.5h.4l.1 .8M90 244.8h-.4l-.2 .2 .2 .3 .4-.1M90.6 244.6l.2-.1h.3v.8M90.6 244.5v.8M92.3 244.5h-.4l-.2 .2 .1 .5h.5M92.3 244v1.3"/>
</g>
<g fill="none" stroke="#000" stroke-width=".18">
<path d="M121.7 27l.7 .8M122.4 27l-.7 .8M129.9 34.8h-.3l-.2 .2 .1 .1 .4 .2v.3h-.5M131.1 34.8h-.4l-.2 .2 .1 .6h.5M131.6 34.9l.2-.1h.3l.1 .8M131.6 34.4v1.2M221.3 23.2v.7l.3 .1 .2-.1M221.8 23.2v.8M222.2 23.2h.5M222.4 22.7v1.1l.3 .2M223.6 23.2h-.3l-.2 .1 .1 .2 .4 .1v.3h-.5M225.1 31h-.2l-.2 .2v.1l.4 .2v.3h-.4"/>
<path d="M226.3 31h-.4l-.2 .2 .1 .6h.5M226.3 25.7l.2-.2 .3 .1 .1 .8M226.3 28.2l.2-.1h.3l.1 .8M226.3 25.5v.9M226.3 28.1v.8M226.8 31.1l.2-.1h.3l.1 .8M226.8 30.5v1.3M240.2 26.4h.8M133.7 53.7l-.4-.1-.2 .3 .1 .5h.5M134.1 53.6h.5M134.3 53.2v1.1l.3 .2M135 53.8l.2-.2 .3 .2 .1 .4-.1 .2-.3 .1-.2-.2z"/>
<path d="M136.1 53.6v.9M136.5 53.6l-.3 .1-.1 .2M170.3 59l.6-.1-.1-.3h-.3l-.2 .1 .1 .6h.4M176.3 51.8l.4-1.3 .4 1.3M176.4 51.4h.6M176.5 53.7l.5-.1 .1-.4-.6-.2v1.3h.5l.1-.1 .1-.3-.3-.2M273.4 55.2l-.3-.1-.2 .2 .1 .2 .4 .1v.3h-.5M274 47.3h-.3l-.3 .2 .1 .6h.5M274.5 47.7l.6-.1v-.3h-.4l-.2 .2 .1 .6h.5M274.6 55.2l-.4-.1-.2 .2 .1 .6h.5M275.1 55.2l.2-.1 .3 .1 .1 .7M275.1 54.7v1.2"/>
<path d="M276.1 47.3h-.3l-.2 .2 .1 .1 .4 .2v.3h-.5M131.2 61.5h-.3l-.2 .1 .1 .2 .4 .1v.3h-.5M132.3 61.5h-.3l-.3 .2 .2 .5h.4M132.9 61.6l.1-.1h.3l.1 .8M132.9 61v1.3M31.3 85.4h.3l.2 .1 .1 .5-.2 .2h-.3l-.1-.1zM32.4 85.5l.2-.1h.3l.1 .8M32.4 85.4v.8M39.7 94.5h-.3l-.2 .2 .1 .1 .4 .2v.3h-.5M40.9 94.5h-.4l-.2 .2 .1 .6h.5M41.4 94.6l.2-.1h.3l.1 .8M41.4 94v1.3"/>
<path d="M90.2 95.8l.6-.1v-.3h-.4l-.2 .2 .1 .6h.5M91.2 95.4h.5M91.4 95v1l.3 .2M196.5 82.9l.3-.1 .3 .3-.1 .5h-.5M196.5 82.8v1.3M199 94.4l.2-.1h.3v.8M199 94.3v.8M205.5 89.4h-.3l-.2 .2 .1 .1 .4 .2v.3h-.5M206.7 89.4h-.4l-.3 .2 .2 .6h.5M207.2 89.5l.2-.1h.3v.8M207.2 89v1.2M214.3 85.3l.3-.1 .3 .3-.1 .5h-.5"/>
<path d="M214.3 85.2v1.3M216.7 96.8l.2-.1h.3l.1 .8M216.7 96.7v.8M31.9 107h.5M32.1 106.5v1.1l.3 .2M32.8 106.5v.2M32.8 107v.8M33.5 107h.3l.3 .2-.2 .6h-.3l-.2-.2zM34.6 107.1l.2-.1h.3v.8M34.6 107v.8M38.5 116.1h-.3l-.2 .1v.2l.5 .1v.4h-.5M39.6 116.1h-.4l-.2 .2 .1 .6h.5"/>
<path d="M40.2 116.2l.1-.1h.3l.1 .8M40.2 115.6v1.3M43 109.4h.5M47.4 111.5h.7M83.8 102.7a.6 .6 0 0 0-.8 .4 .6 .6 0 0 0 .6 .7l.2-.1M198.6 114.6h-.3l-.1 .2M199 114.6h.5v.8M199.5 114.9h-.4l-.2 .2 .1 .3h.5M199.7 104.5l-.3-.1-.2 .3 .1 .5h.4M200.1 104.4h.5M200.3 104v1.1l.3 .2M205.5 100.9l-.3-.1-.2 .2 .1 .2 .4 .1v.3h-.5"/>
<path d="M205.5 111h-.3l-.2 .2 .1 .1 .4 .2v.3h-.5M206.7 100.9l-.4-.1-.3 .3 .2 .5h.5M206.7 111h-.4l-.3 .2 .2 .6h.5M207.2 101l.2-.2 .3 .1v.8M207.2 111.1l.2-.1h.3v.8M207.2 100.4v1.3M207.2 110.6v1.2M216 117.4l.6-.1-.1-.3h-.3l-.2 .2v.6h.5M216.9 117h.5M217.1 116.5v1.1l.3 .2M217.5 106.9l-.3-.1-.3 .2 .1 .6h.5M217.9 106.8h.5"/>
<path d="M218.1 106.4v1.1l.3 .2M31.6 127.2l.3-.3v1.2M31.6 128.1h.7M33.5 126.9h-.7v.6l.2-.2 .5 .2v.5l-.2 .1-.5-.1M39.7 136.4h-.3l-.2 .2 .1 .1 .4 .2v.3h-.5M40.9 136.4h-.4l-.2 .2 .1 .6h.5M41.4 136.5l.2-.1h.3l.1 .8M41.4 136v1.2M42.5 133.1v-1.3l.5 .9 .4-.9v1.3M54.8 132.4l.6-.1 .1-.2-.1-.2-.6-.1v1.3h.5l.2-.2v-.3l-.3-.2M145.1 138.7l.2-.1h.3l.1 .8M205.5 121.2l-.3-.1-.2 .2 .1 .2 .4 .1v.3h-.5"/>
<path d="M206.7 121.2l-.4-.1-.3 .3 .2 .5h.5M207.2 121.3l.2-.2 .3 .1v.8M207.2 120.7v1.3M31.6 143.4h.9l-.6 1.2M32.8 144.6l.4-1.2 .4 1.2M32.9 144.3h.6M39.7 152.9h-.3l-.2 .2 .1 .1 .4 .2v.3h-.5M40.9 152.9h-.4l-.2 .2 .1 .6h.5M41.4 153l.2-.1h.3l.1 .8M41.4 152.5v1.2M54.8 149.6l.4-1.3 .5 1.3M133.6 141.2l.3-.1 .3 .2-.2 .6h-.4"/>
<path d="M133.6 140.7v1.2M134 146.3l.2-.1h.3l.1 .8M134 148.9l.2-.2 .3 .1 .1 .8M134 146.2v.8M134 148.7v.9M138.5 153.9l-.4-.1-.2 .2 .1 .6h.5M138.7 151.3h-.4l-.2 .2 .1 .6h.5M145.4 141.1h.4M145.5 140.7v1.1l.3 .1M29.7 166.2h-.2a.79 .79 0 0 0-.2 1.3l.5-.1v-.6l-.5-.1-.2 .3M30.2 167.5l.4-1.3 .4 1.3M30.3 167.1h.6"/>
<path d="M37.2 175.8h-.3l-.2 .1 .1 .2 .4 .1v.3h-.5M38.4 175.8h-.4l-.3 .2 .2 .5h.5M38.9 175.9l.2-.1h.3v.8M38.9 175.3v1.3M42.2 171.7l.2-.1h.3v.8M42.2 171.6v.8M46.4 169.2l.2-.2 .3 .1 .1 .8M46.4 169v.9M56.1 172.4h.7M29.5 181.4l-.3 .9h.8M29.8 181.9v.8M30.4 181.5h.8l-.5 1.2"/>
<path d="M37.2 191h-.3l-.2 .2 .1 .1 .4 .2v.3h-.5M38.4 191h-.4l-.3 .2 .2 .6h.5M38.9 191.1l.2-.1h.3v.8M38.9 190.6v1.2M42.2 187l.2-.2 .3 .1v.8M42.2 186.8v.9M46.4 184.4l.2-.1h.3l.1 .8M46.4 184.3v.8"/>
</g>
<g fill="none" stroke="#0000c2" stroke-width=".18" stroke-dasharray=".4 .4">
<path d="M12.7 16.5v50.8M12.7 16.5h81.3M100.3 15.3h288.3M153.7 15.3v52M204.5 15.3v52M336.5 15.3v52M388.6 15.3v52M100.3 41.9h53.4M204.5 43.2h40.6M12.7 67.3h81.3M15.2 71.2h43.2M15.2 71.2v124.4"/>
<path d="M58.4 71.2v124.4M62.2 71.2v128.2M94 67.3v-50.8M100.3 67.3v-52M100.3 67.3h288.3M176.5 71.2h-114.3M182.9 73.7v55.9M229.9 72.4h-47M245.1 67.3v-52M278.1 96.6h31.8M309.9 96.6v50.8M363.2 95.3v40.6"/>
<path d="M398.8 95.3h-35.6M15.2 100.4h43.2M15.2 120.7h43.2M182.9 129.6h47M229.9 129.6v-57.2M363.2 135.9h35.6M398.8 135.9v-40.6M15.2 158.8h43.2M190.5 156.2v20.4M218.4 156.2h-27.9M257.8 149.9h147.3M278.1 147.4v-50.8"/>
<path d="M309.9 147.4h-31.8M313.7 149.9v91.4M405.1 149.9v91.4M190.5 176.6h27.9M218.4 176.6v-20.4M15.2 195.6h43.2M62.2 199.4h114.3M176.5 199.4v-128.2M15.2 203.2h82.6M15.2 203.2v80M97.8 203.2v80M102.9 208.3v74.9"/>
<path d="M179.1 208.3v74.9M247.6 207h-144.7M15.2 242.6h82.6M257.8 241.3v-91.4M405.1 241.3h-147.3M15.2 283.2h82.6M102.9 283.2h144.7M247.6 283.2v-76.2"/>
</g>
<g fill="none" stroke="#000084" stroke-width=".18">
<path d="M42.6 31.2l1.2 1.2M43.8 31.2l-1.2 1.2M42.6 49l1.2 1.2M42.6 54l1.2 1.3M42.6 51.5l1.2 1.2M43.8 49l-1.2 1.2M43.8 54l-1.2 1.3M43.8 51.5l-1.2 1.2M296.6 107.4l1.2 1.2M297.8 107.4l-1.2 1.2M90.8 126.4l1.2 1.2M90.8 129l1.2 1.2"/>
<path d="M90.8 131.5l1.2 1.2M90.8 134l1.2 1.3M90.8 136.6l1.2 1.2M90.8 139.1l1.2 1.2M92 126.4l-1.2 1.2M92 129l-1.2 1.2M92 131.5l-1.2 1.2M92 134l-1.2 1.3M92 136.6l-1.2 1.2M92 139.1l-1.2 1.2M296.6 126.4l1.2 1.2M297.8 126.4l-1.2 1.2"/>
<path d="M379.1 176l1.2 1.2M380.3 176l-1.2 1.2M341 193.7l1.2 1.3M342.2 193.7l-1.2 1.3M391.8 183.6l1.2 1.2M391.8 186.1l1.2 1.2M391.8 191.2l1.2 1.2M393 183.6l-1.2 1.2M393 186.1l-1.2 1.2M393 191.2l-1.2 1.2M356.3 203.9l1.2 1.2M356.3 206.4l1.2 1.3"/>
<path d="M356.3 209l1.2 1.2M356.3 211.5l1.2 1.2M356.3 216.6l1.2 1.2M357.5 203.9l-1.2 1.2M357.5 206.4l-1.2 1.3M357.5 209l-1.2 1.2M357.5 211.5l-1.2 1.2M357.5 216.6l-1.2 1.2M391.8 216.6l1.2 1.2M391.8 214.1l1.2 1.2M391.8 211.5l1.2 1.2M391.8 206.4l1.2 1.3"/>
<path d="M393 216.6l-1.2 1.2M393 214.1l-1.2 1.2M393 211.5l-1.2 1.2M393 206.4l-1.2 1.3M48.9 222.9l1.2 1.3M50.1 222.9l-1.2 1.3M120 240.7l1.3 1.2M120 243.3l1.3 1.2M120 245.8l1.3 1.2M120 256l1.3 1.2M121.3 240.7l-1.3 1.2M121.3 243.3l-1.3 1.2"/>
<path d="M121.3 245.8l-1.3 1.2M121.3 256l-1.3 1.2M150.5 240.7l1.2 1.2M150.5 243.3l1.2 1.2M151.7 240.7l-1.2 1.2M151.7 243.3l-1.2 1.2"/>
</g>
<g fill="none" stroke="#840000" stroke-width=".51">
<path d="M14.5 36.4h4M14.5 34.8h4M306.6 31.3h4M306.6 29.8h4M306.6 57.9h4M306.6 56.4h4M381.5 166.9h4.1M381.5 168.4h4.1M391.7 166.9h4M391.7 168.4h4M295.3 186.1v3.8M295.3 201.3v3.8"/>
<path d="M28.4 227.9h4.1M28.4 229.4h4.1M88.1 227.9h4.1M88.1 229.4h4.1M140.2 226.9h4.1M140.2 225.3h4.1M220.2 224.3h4.1M220.2 222.8h4.1M33.5 267.2h4.1M33.5 268.8h4.1M45 267.2h4M45 268.8h4"/>
<path d="M79.2 267.2h4.1M79.2 268.8h4.1"/>
</g>
<g fill="#008400" stroke="#008400" stroke-width=".25">
<circle cx="215.9" cy="219.7" r=".51"/>
<circle cx="375.9" cy="227.4" r=".51"/>
<circle cx="369.6" cy="163.9" r=".51"/>
<circle cx="374.6" cy="163.9" r=".51"/>
<circle cx="281.9" cy="203.2" r=".51"/>
<circle cx="276.9" cy="188" r=".51"/>
<circle cx="137.2" cy="265.5" r=".51"/>
<circle cx="135.9" cy="222.3" r=".51"/>
<circle cx="135.9" cy="233.7" r=".51"/>
<circle cx="342.9" cy="196.9" r=".51"/>
<circle cx="334" cy="189.3" r=".51"/>
<circle cx="345.4" cy="199.4" r=".51"/>
<circle cx="308.6" cy="53.4" r=".51"/>
<circle cx="54.6" cy="260.4" r=".51"/>
<circle cx="35.6" cy="260.4" r=".51"/>
<circle cx="47" cy="260.4" r=".51"/>
<circle cx="81.3" cy="260.4" r=".51"/>
<circle cx="50.8" cy="260.4" r=".51"/>
<circle cx="26.7" cy="28" r=".51"/>
<circle cx="383.5" cy="163.9" r=".51"/>
<circle cx="63.5" cy="233.7" r=".51"/>
<circle cx="83.8" cy="228.6" r=".51"/>
<circle cx="30.5" cy="219.7" r=".51"/>
<circle cx="83.8" cy="219.7" r=".51"/>
<circle cx="90.2" cy="219.7" r=".51"/>
<circle cx="379.7" cy="108" r=".51"/>
<circle cx="384.8" cy="108" r=".51"/>
<circle cx="375.9" cy="108" r=".51"/>
<circle cx="308.6" cy="26.7" r=".51"/>
<circle cx="304.8" cy="137.2" r=".51"/>
</g>
<g fill="none" stroke="#840000" stroke-width=".25">
<path d="M57.1 30.5h7.7l3.8-3.8h1.2v1.3h2.6l1.3-1.3h12.7v24.1h-29.3zM82.5 26.7v-1.3h-35.5v33.1h35.5v-7.7M185.4 26.7h2.6v10.2h-2.6zM186.7 50.8h2.5v10.2h-2.5zM223.5 53.4h2.6v10.1h-2.6zM94 94h25.4v66.1h-25.4zM367.3 116.9h2v5.1h-2zM374.9 116.9h2v5.1h-2zM383.8 116.9h2v5.1h-2zM391.4 116.9h2v5.1h-2zM198.1 166.7h5.1v2h-5.1zM359.4 179.1h30.5v43.2h-30.5z"/>
<path d="M283.2 187h5.1v2h-5.1zM328.9 191.8h10.2v15.2h-10.2zM283.2 202.2h5.1v2.1h-5.1zM330.8 201.6h.7l1.2 1.3h.7M332.1 201.6h2.5M334 200.3h-1.3l-.6 1.3h-.6M82.8 229.9h2v5.1h-2zM82.8 222.3h2v5.1h-2zM124.5 237.5h22.8v22.9h-22.8zM208.3 233.7h15.2v15.3h-15.2zM59.7 257.8h15.2v10.2h-15.2z"/>
<circle cx="295.9" cy="188" r="2.82"/>
<circle cx="295.9" cy="203.2" r="2.82"/>
</g>
<g fill="#840000" stroke="#840000" stroke-width=".18">
<path d="M295.9 189.8l.5-.5 .5 1z"/>
<path d="M295.9 201.5l1-.5-.5 1z"/>
<path d="M329.9 204.3h2.1l.2 .7h-2.5z"/>
<path d="M58.4 48.9h2.6v1.3h-2.6z"/>
<path d="M58.4 46.4h2.6v1.3h-2.6z"/>
<path d="M58.4 43.9h2.6v1.2h-2.6z"/>
<path d="M58.4 41.3h2.6v1.3h-2.6z"/>
<path d="M58.4 38.8h2.6v1.2h-2.6z"/>
<path d="M58.4 36.2h2.6v1.3h-2.6z"/>
<path d="M58.4 33.7h2.6v1.3h-2.6z"/>
<path d="M58.4 31.2h2.6v1.2h-2.6z"/>
<circle cx="33" cy="255.3" r=".25"/>
<circle cx="326.4" cy="53.4" r=".25"/>
<circle cx="321.3" cy="26.7" r=".25"/>
</g>
<g fill="#ffffc2" stroke="#ffffc2" stroke-width=".18">
<path d="M359.4 179.1h30.5v43.2h-30.5z"/>
<path d="M124.5 237.5h22.8v22.9h-22.8z"/>
<path d="M208.3 233.7h15.2v15.3h-15.2z"/>
<path d="M328.9 191.8h10.2v15.2h-10.2z"/>
<path d="M57.1 30.5h7.7l3.8-3.8h1.2v1.3h2.6l1.3-1.3h12.7v24.1h-29.3z"/>
<path d="M59.7 257.8h15.2v10.2h-15.2z"/>
<path d="M94 94h25.4v66.1h-25.4z"/>
<path d="M185.4 26.7h2.6v10.2h-2.6z"/>
<path d="M52.1 215.9h22.8v15.3h-22.8z"/>
<path d="M186.7 50.8h2.5v10.2h-2.5z"/>
<path d="M223.5 53.4h2.6v10.1h-2.6z"/>
</g>
<g fill="none" stroke="#008484" stroke-width=".18">
<path d="M55.5 33.6a.64 .64 0 0 1 .7 .7 .64 .64 0 0 1-.7 .6zM71.4 23.3h-.4l-.2 .2 .1 .6h.5M71.4 22.8v1.3M199.7 32.3l-.3 .9h.8M200 32.8v.8M200.9 56.5l-.3 .8h.8M201.2 56.9v.9M237.8 59l-.3 .9h.8M238.1 59.5v.8M97.7 81.3h.5M98.3 80.7h-.6v1.2h.6M109.8 98.4h.7"/>
<path d="M110.1 98.4v1.3M114.9 80.8l.5-.1 .2 .3v.2l-.7 .7h.7M159.3 98.9h.5M159.5 98.4v1.1l.3 .2M109.7 104.1h.6l.1-.2-.1-.3-.6-.1v1.2M110 104.1l.4 .6M159.3 111.6h.5M159.3 114.1h.5M159.3 116.6h.5M159.3 119.2h.5M159.3 101.4h.5M159.3 106.5h.5"/>
<path d="M159.3 109h.5M159.3 103.9h.5M159.5 111.1v1.1l.3 .2M159.5 113.7v1.1l.3 .1M159.5 116.2v1.1l.3 .2M159.5 118.8v1l.3 .2M159.5 101v1.1l.3 .1M159.5 106.1v1l.3 .2M159.5 108.6v1.1l.3 .2M159.5 103.5v1.1l.3 .2M302.9 104l-.4-.1-.2 .3 .1 .5h.5M302.9 114.1h-.4l-.2 .2 .1 .6h.5"/>
<path d="M302.9 103.5v1.3M302.9 113.7v1.2M101.7 129.2l.4-.3v1.2M101.7 130.1h.7M102.4 131.5l.5-.1 .2 .4-.7 .9h.7M102.4 137l.5 .8M102.5 133.9h.8l-.5 .5 .4 .2-.1 .6h-.4l-.2-.1M102.6 139a.64 .64 0 0 1 .7 .7 .64 .64 0 0 1-.7 .6zM102.6 126.4l.1-.1a.67 .67 0 0 1 .5 .7 .67 .67 0 0 1-.5 .6 .83 .83 0 0 1-.1-1.2zM102.9 136.5l-.7 .7M159.3 129.3h.5M159.3 126.8h.5"/>
<path d="M159.3 124.3h.5M159.3 121.7h.5M159.3 134.4h.5M159.3 131.9h.5M159.5 128.9v1.1l.3 .2M159.5 126.4v1.1l.3 .1M159.5 123.8v1.1l.3 .2M159.5 121.3v1.1l.3 .2M159.5 134v1.1l.3 .2M159.5 131.5v1l.3 .2M302.9 123h-.4l-.2 .2 .1 .6h.5M302.9 133.2l-.4-.1-.2 .3 .1 .5h.5"/>
<path d="M302.9 122.5v1.3M302.9 132.7v1.3M159.3 152.2h.5M159.3 154.7h.5M159.3 149.7h.5M159.3 147.1h.5M159.5 151.8v1.1l.3 .1M159.5 154.3v1.1l.3 .2M159.5 149.2v1.1l.3 .2M159.5 146.7v1.1l.3 .2M342.7 176.8v.5M343.5 176.8l-.2 .3h-1.1"/>
<path d="M345.2 176.8v.5M346 176.8l-.1 .3h-1.1M335.5 196.2a.64 .64 0 0 1 .7 .6 .64 .64 0 0 1-.7 .6zM336.7 197h1M360.8 196.2a.64 .64 0 0 1 .7 .6 .64 .64 0 0 1-.7 .6zM362.1 197h.9M379 186.2l1.3 .4-1.3 .4M56.7 219.6l.2-.1h.3l.1 .8M33.7 229.3l.4-.3v1.3M33.7 230.3h.7M42.8 229l.5 1.3 .4-1.3M66.4 223.3h.5"/>
<path d="M66.9 222.8l-.3 .2v1.1M67.1 223.3h.5M67.6 222.8l-.3 .2v1.1M132.8 240.8l.2-.2a.69 .69 0 0 1 .4 .7 .69 .69 0 0 1-.4 .6l-.2-.2-.1-.3zM215.9 241.9l.4-1.3 .4 1.3M216 241.5h.6M224.6 243.1v-1.3l.4 .9 .5-.9v1.3M237.2 243.1l.4-1.3 .4 1.3M237.3 242.7h.6M18.7 266.9v.5M19.5 266.9l-.1 .3h-1.1"/>
</g>
<g fill="none" stroke="#840000" stroke-width="1.3">
<circle cx="293.4" cy="108" r="1.27"/>
<circle cx="293.4" cy="118.1" r="1.27"/>
<circle cx="293.4" cy="127" r="1.27"/>
<circle cx="293.4" cy="137.2" r="1.27"/>
</g>
<g fill="none" stroke="#840084" stroke-width=".18">
<path d="M113 28h15.3v6.3h-15.3zM208.3 24.2h15.2v6.3h-15.2zM114.3 54.6h15.2v6.4h-15.2zM256.5 48.3h15.3v6.3h-15.3zM19 86.4h22.9v7.6h-22.9zM188 83.9h13.9v5h-13.9zM188 95.3h13.9v5.1h-13.9zM17.8 108h22.8v7.6h-22.8zM188 105.4h13.9v5.1h-13.9zM188 115.6h13.9v5.1h-13.9zM19 128.3h22.9v7.6h-22.9zM19 144.8h22.9v7.6h-22.9z"/>
<path d="M16.5 167.7h22.9v7.6h-22.9zM16.5 182.9h22.9v7.6h-22.9z"/>
</g>
<g fill="none" stroke="#848400" stroke-width=".18">
<path d="M116.3 32.8v1.1l-.2 .1h-.3M116.3 32.8h-.3l-.3 .2 .1 .6h.5M116.3 30.2v1.2l-.2 .1-.3-.1M116.3 30.3l-.3-.1-.3 .3 .1 .5h.5M125.7 33.6h.7M211.6 29l-.1 1.1-.2 .1h-.3M211.6 29h-.4l-.2 .2 .1 .6h.5M211.6 26.4l-.1 1.2-.2 .1-.3-.1M211.6 26.5l-.4-.1-.2 .3 .1 .5h.5M220.9 29.8h.8M117.6 59.4l-.1 1.2-.2 .1-.3-.1M117.6 59.5l-.4-.1-.2 .3 .1 .5h.5"/>
<path d="M117.6 56.9l-.1 1.2-.2 .1-.3-.1M117.6 57l-.4-.1-.2 .2 .1 .6h.5M259.8 53.1v1.1l-.2 .2-.3-.1M259.8 53.1h-.3l-.3 .2 .1 .6h.5M259.8 50.6v1.1l-.2 .1h-.3M259.8 50.6h-.3l-.3 .2 .1 .5h.5M269.2 53.9h.7M126.9 60.3h.8M21.5 88.7h.4l.2 .2-.1 .5h-.5M21.5 88.7v1.2M27.2 91.2v.8M27.6 91.2l-.4 .2"/>
<path d="M39.7 91.2h.5M39.7 88.7h.5M39.9 90.8v1.1l.3 .1M39.9 88.2v1.1l.3 .2M191.7 86.2l.4-.1 .2 .2-.1 .6h-.5M191.7 97.6l.4-.1 .2 .3-.1 .5h-.5M191.7 86.1v1.3M191.7 97.5v1.3M20.3 110.3l.4-.1 .2 .3-.1 .5h-.5M20.3 110.2v1.3M26 112.8v.8M26.3 112.8l-.3 .2"/>
<path d="M38.4 112.8h.5M38.4 110.2h.5M38.6 112.4v1l.3 .2M38.6 109.8v1.1l.3 .2M191.7 107.8l.4-.1 .2 .2-.1 .6h-.5M191.7 117.9h.4l.2 .2-.1 .6h-.5M191.7 107.7v1.3M191.7 117.9v1.2M21.5 130.6h.4l.2 .2-.1 .6h-.5M21.5 130.6v1.2M27.2 133.1v.8M27.6 133.1l-.4 .2"/>
<path d="M39.7 133.1h.5M39.7 130.6h.5M39.9 132.7v1.1l.3 .1M39.9 130.1v1.1l.3 .2M21.5 147.1h.4l.2 .2-.1 .6h-.5M21.5 147.1v1.2M27.2 149.6v.9M27.6 149.6l-.4 .2M39.7 149.6h.5M39.7 147.1h.5M39.9 149.2v1.1l.3 .2M39.9 146.6v1.1l.3 .2"/>
<path d="M19 170l.4-.1 .2 .3-.1 .5h-.5M19 169.9v1.3M24.7 172.5v.8M25.1 172.5l-.4 .2M37.2 172.5h.4M37.2 169.9h.4M37.3 172v1.1l.3 .2M37.3 169.5v1.1l.3 .2M19 185.2h.4l.2 .2-.1 .6h-.5M19 185.2v1.2M24.7 187.7v.9M25.1 187.7l-.4 .2"/>
<path d="M37.2 187.7h.4M37.2 185.2h.4M37.3 187.3v1.1l.3 .2M37.3 184.7v1.1l.3 .2"/>
</g>
<g fill="none" stroke="#848400" stroke-width=".25">
<path d="M127.6 32.4h.7v1.3h-.7l-.6-.6zM127.6 29.9h.7v1.3h-.7l-.6-.7zM222.9 28.6h.6v1.3h-.6l-.7-.7zM222.9 26.1h.6v1.2h-.6l-.7-.6zM128.9 59.1h.6v1.3h-.6l-.6-.7zM128.9 56.6h.6v1.2h-.6l-.6-.6zM271.1 52.7h.7v1.3h-.7l-.6-.6zM271.1 50.2h.7v1.3h-.7l-.6-.7zM41.3 90.8h.6v1.3h-.6l-.7-.6zM41.3 88.3h.6v1.3h-.6l-.7-.7zM201.3 85.8h.6v1.2h-.6l-.6-.6zM201.3 97.2h.6v1.3h-.6l-.6-.7z"/>
<path d="M40 112.4h.6v1.3h-.6l-.6-.6zM40 109.9h.6v1.3h-.6l-.6-.7zM201.3 107.4h.6v1.2h-.6l-.6-.6zM201.3 117.5h.6v1.3h-.6l-.6-.7zM41.3 132.8h.6v1.2h-.6l-.7-.6zM41.3 130.2h.6v1.3h-.6l-.7-.7zM41.3 149.3h.6v1.2h-.6l-.7-.6zM41.3 146.7h.6v1.3h-.6l-.7-.6zM38.7 172.1h.7v1.3h-.7l-.6-.6zM38.7 169.6h.7v1.3h-.7l-.6-.7zM38.7 187.4h.7v1.2h-.7l-.6-.6zM38.7 184.8h.7v1.3h-.7l-.6-.6z"/>
</g>
<g fill="#840000" stroke="#840000" stroke-width=".25">
<path d="M333.5 199.9h.8v.8h-.8z"/>
<path d="M334.6 201l1.3 .6-1.3 .6z"/>
<circle cx="330.2" cy="201.6" r=".63"/>
<circle cx="333.4" cy="202.9" r=".38"/>
</g>
<path d="M207 166.4l2.5 1.3-2.5 1.2zM209.5 166.4v2.5" fill="none" stroke="#840000" stroke-width=".2"/>
<use href="#words"/>
</svg>
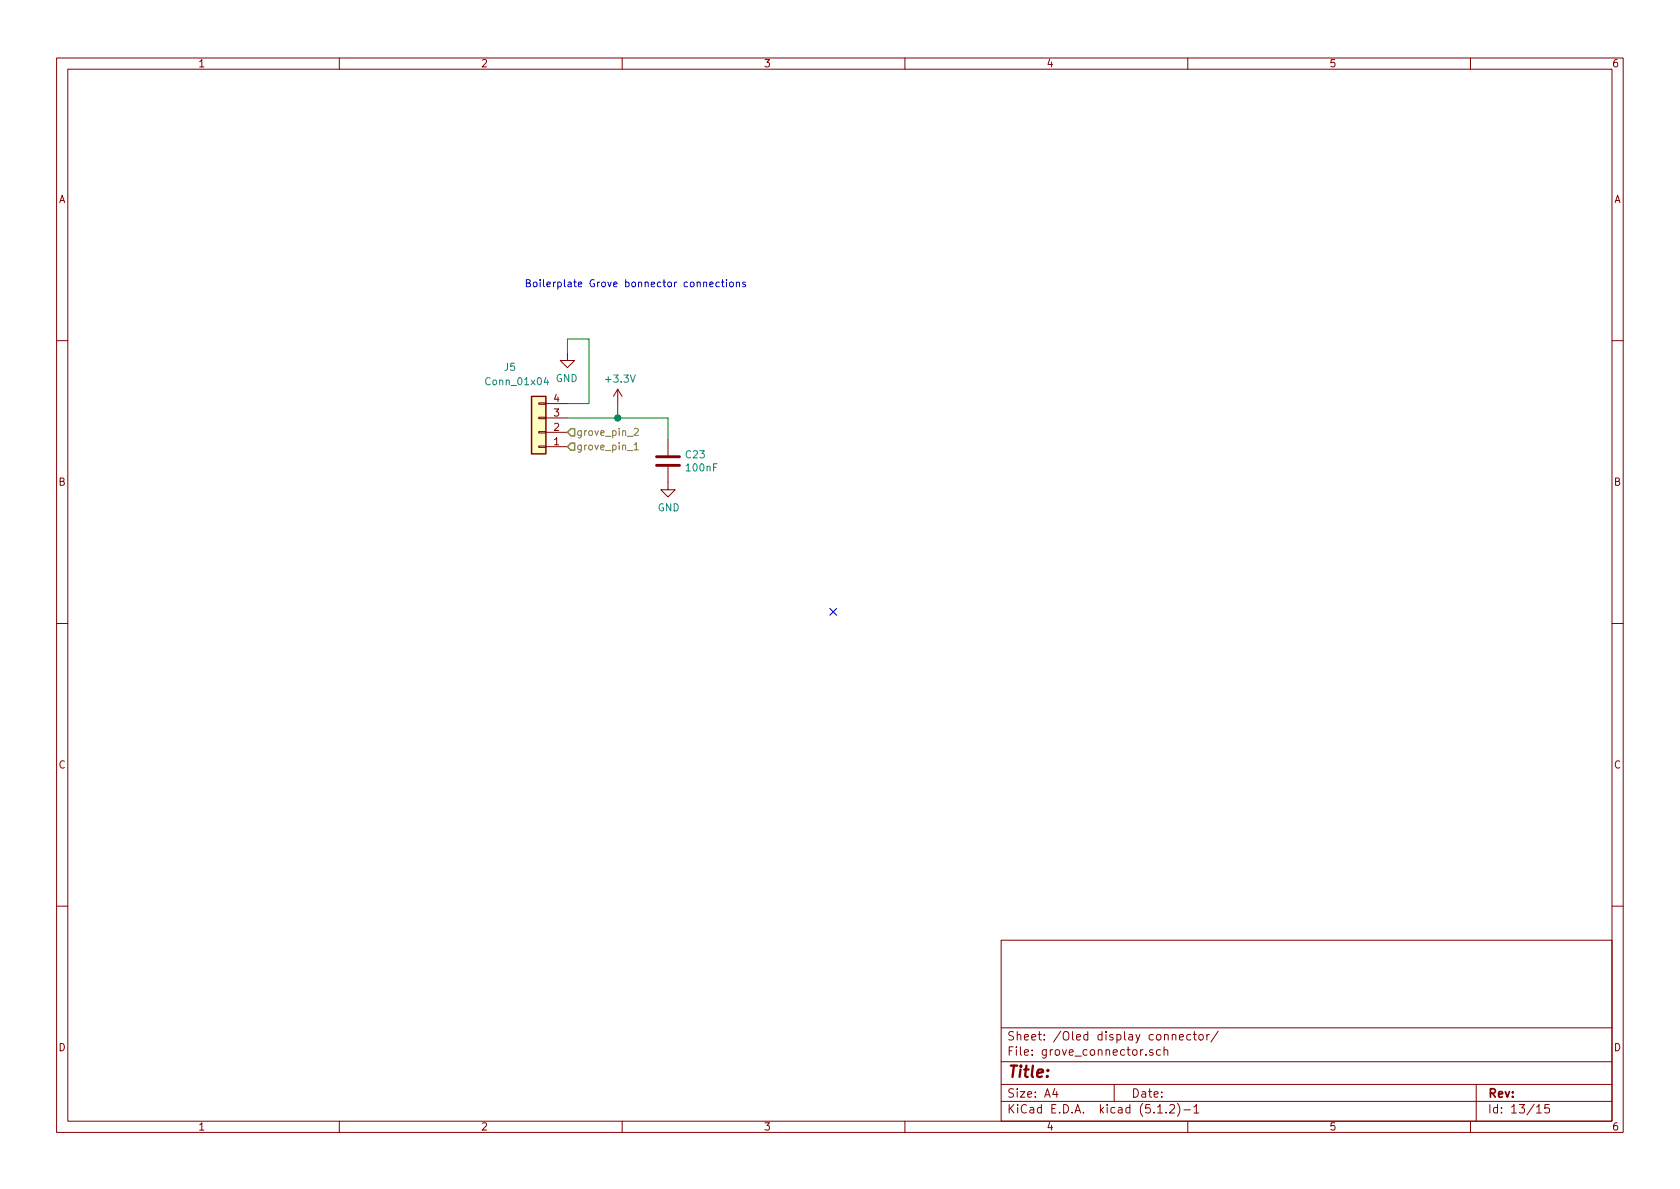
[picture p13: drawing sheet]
<svg xmlns="http://www.w3.org/2000/svg" width="297mm" height="210mm" viewBox="0 0 297 210" stroke-linecap="round" stroke-linejoin="round" font-family="sans-serif">
<defs><g id="words">
<text font-size="2.8" fill="#840000" x="178" y="190.5">Title:</text>
<g font-size="2.1" fill="#840000">
<text x="178" y="184">Sheet: /Oled display connector/</text>
<text x="178" y="186.7">File: grove_connector.sch</text>
<text x="178" y="196.9">KiCad E.D.A. kicad (5.1.2)-1</text>
<text x="178" y="194.1">Size: A4</text>
<text x="200" y="194.1">Date:</text>
<text x="263" y="194.1">Rev:</text>
<text x="263" y="196.9">Id: 13/15</text>
</g>
<g font-size="1.8" fill="#840000">
<text x="35" y="11.9">1</text>
<text x="85" y="11.9">2</text>
<text x="135" y="11.9">3</text>
<text x="185" y="11.9">4</text>
<text x="235" y="11.9">5</text>
<text x="285" y="11.9">6</text>
<text x="10.4" y="35.9">A</text>
<text x="285.4" y="35.9">A</text>
<text x="97.9" y="71.1">4</text>
<text x="97.9" y="76.2">2</text>
<text x="97.9" y="73.7">3</text>
<text x="97.9" y="78.7">1</text>
<text x="10.4" y="85.9">B</text>
<text x="285.4" y="85.9">B</text>
<text x="10.4" y="135.9">C</text>
<text x="285.4" y="135.9">C</text>
<text x="10.4" y="185.9">D</text>
<text x="285.4" y="185.9">D</text>
<text x="35" y="199.9">1</text>
<text x="85" y="199.9">2</text>
<text x="135" y="199.9">3</text>
<text x="185" y="199.9">4</text>
<text x="235" y="199.9">5</text>
<text x="285" y="199.9">6</text>
</g>
<text font-size="1.8" fill="#0000c2" x="92.7" y="50.8">Boilerplate Grove bonnector connections</text>
<g font-size="1.8" fill="#008484">
<text x="89.2" y="65.6">J5</text>
<text x="86.2" y="68.1">Conn_01x04</text>
<text x="98.2" y="67.6">GND</text>
<text x="107.3" y="67.7">+3.3V</text>
<text x="121.3" y="81">C23</text>
<text x="121.5" y="83.4">100nF</text>
<text x="116.3" y="90.4">GND</text>
</g>
<g font-size="1.8" fill="#848400">
<text x="101.9" y="77.1">grove_pin_2</text>
<text x="101.9" y="79.6">grove_pin_1</text>
</g>
</g></defs>
<g fill="none" stroke="#840000" stroke-width=".18">
<path d="M10 10.3h277v189.9h-277zM12 12.2h273v186.1h-273zM60 10.3v1.9M110 10.3v1.9M160 10.3v1.9M210 10.3v1.9M260 10.3v1.9M10 60.2h2M95.2 71.2h1.3v.3h-1.3zM95.2 73.8h1.3v.2h-1.3zM95.2 76.3h1.3v.3h-1.3zM95.2 78.9h1.3v.2h-1.3z"/>
<path d="M96.5 79h3.8M96.5 76.4h3.8M96.5 73.9h3.8M96.5 71.4h3.8M100.3 62.5v1.2h-1.2l1.2 1.3 1.3-1.3h-1.3M109.2 68.8l-.7 1.3M109.2 68.8v2.6M109.2 68.8l.8 1.3M118.1 77.7v2.8M285 60.2h2M118.1 82.5v4.1h1.3l-1.3 1.3-1.3-1.3h1.3M10 110.3h2"/>
<path d="M285 110.3h2M10 160.2h2M177 166.3h108v32h-108zM285 160.2h2M60 198.3v1.9M110 198.3v1.9M160 198.3v1.9M177 194.8h108M177 191.8h108M177 187.8h108M177 181.8h108M186.5 192.5l-.4 1h1"/>
<path d="M186.8 193v1M197 191.8v3M202.6 186.5v.1M203.8 185.7a.37 .37 0 0 0-.5 .1v.2l.5 .2 .1 .1-.2 .3-.4-.1M204.7 196.8h.8M205.2 185.7l-.5-.1-.2 .3v.6l.2 .1 .5-.1M205.8 185.7h.1a.37 .37 0 0 1 .6 .1v.8M205.8 185.1v1.5M206.2 196.7v.1M206.8 195.5l.2-.2h.4l.2 .2 .1 .3-.1 .2-.8 .8h.9M207.3 183.1v-.1a.37 .37 0 0 1 .6 .1v.8M208.2 195.1a1.71 1.71 0 0 1 0 2.3"/>
<path d="M208.5 183.4l.7-.1v-.3l-.4-.1-.3 .2 .1 .7h.6M209.3 196.3h1.2M210 198.3v1.9M210.5 183l-.4-.1-.3 .3 .2 .6h.5M211 182.9h.5M211.1 195.8l.4-.5v1.5M211.1 196.8h.9M211.2 182.4v1.3l.3 .2M212 183.1l.2-.2 .5 .2v.7l-.2 .1-.5-.1zM213.4 182.9v1M213.8 182.9l-.4 .3M215.4 182.3l-1.3 2"/>
<path d="M260 198.3v1.9M261 191.8v6.5M271.7 195.8l.4-.5v1.5M271.7 196.8h.8M273.9 195.3h-.7l-.1 .7 .2-.1 .5 .1 .2 .2-.1 .5-.2 .1-.6-.1"/>
</g>
<path d="M100.3 62.5v-2.6h3.8v11.5h-3.8M100.3 73.9h17.8v3.8M109.2 71.4v2.5" fill="none" stroke="#008400" stroke-width=".18"/>
<path d="M94 70.1h2.5v10.2h-2.5z" fill="#ffffc2" stroke="#ffffc2" stroke-width=".18"/>
<path d="M94 70.1h2.5v10.2h-2.5z" fill="none" stroke="#840000" stroke-width=".25"/>
<path d="M96.5 66.7l-.3 .9h.8M96.8 67.2v.8" fill="none" stroke="#008484" stroke-width=".18"/>
<path d="M116.1 82.3h4M116.1 80.8h4" fill="none" stroke="#840000" stroke-width=".51"/>
<circle cx="109.2" cy="73.9" r=".51" fill="#008400" stroke="#008400" stroke-width=".25"/>
<path d="M110.9 79.7h1M112.1 78.6l.4-.3v1.2M112.1 75.9l.5-.2 .3 .4-.1 .2-.7 .7h.8M112.1 79.5h.8" fill="none" stroke="#848400" stroke-width=".18"/>
<path d="M100.3 76.4l.7-.6h.6v1.3h-.6zM101 78.4h.6v1.2h-.6l-.7-.6z" fill="none" stroke="#848400" stroke-width=".25"/>
<path d="M146.7 107.6l1.2 1.2M147.9 107.6l-1.2 1.2" fill="none" stroke="#000084" stroke-width=".18"/>
<path d="M125.5 50.3l.6-.1-.1-.3h-.3l-.2 .2 .1 .6h.4M127.2 49.9h-.4l-.2 .2 .1 .6h.5M127.6 49.9h.4M127.7 49.4v1.1l.3 .2M128.4 49.4v.2M128.4 49.9v.8M129.1 49.9h.3l.2 .1 .1 .5-.2 .2h-.3l-.1-.1zM130.2 50l.2-.1h.3l.1 .8M130.2 49.9v.8M131.8 49.9h-.3l-.2 .2 .1 .1 .4 .2v.3h-.5" fill="none" stroke="#0000c2" stroke-width=".18"/>
<use href="#words"/>
</svg>
